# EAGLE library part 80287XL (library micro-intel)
MICROCOMPUTER/PERIPHERAL DEVICE

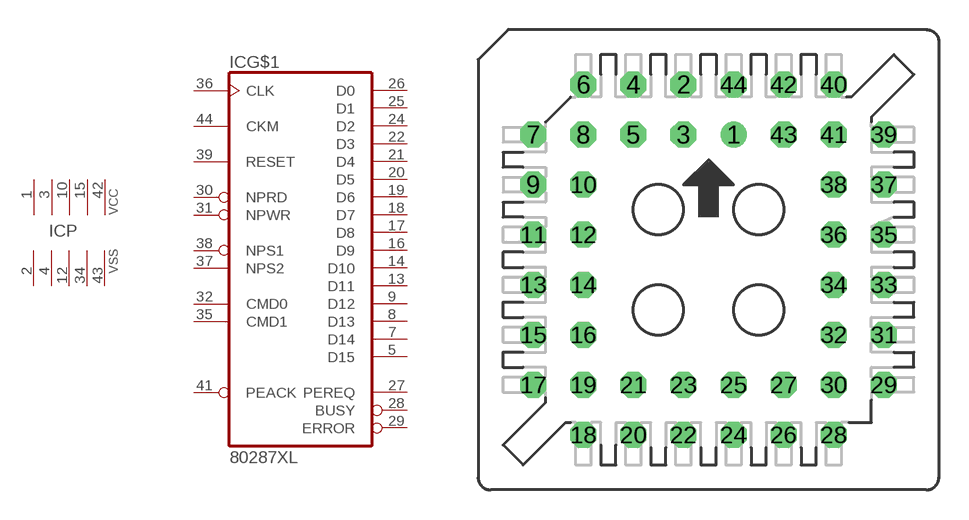
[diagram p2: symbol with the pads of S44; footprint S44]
Designator prefix IC; gates G$1=80287XL P=5VCC5VSS

## 80287XL (OC_FARNELL: unknown; OC_NEWARK: unknown)  [S44]
1  P:VCC  pwr
2  P:VSS  pwr
3  P:VCC  pwr
4  P:VSS  pwr
5  G$1:D15
7  G$1:D14
8  G$1:D13
9  G$1:D12
10  P:VCC  pwr
12  P:VSS  pwr
13  G$1:D11
14  G$1:D10
15  P:VCC  pwr
16  G$1:D9
17  G$1:D8
18  G$1:D7
19  G$1:D6
20  G$1:D5
21  G$1:D4
22  G$1:D3
24  G$1:D2
25  G$1:D1
26  G$1:D0
27  G$1:PEREQ  out
28  G$1:BUSY  out
29  G$1:ERROR  out
30  G$1:NPRD  in
31  G$1:NPWR  in
32  G$1:CMD0  in
34  P:VSS  pwr
35  G$1:CMD1  in
36  G$1:CLK  in
37  G$1:NPS2  in
38  G$1:NPS1  in
39  G$1:RESET  in
41  G$1:PEACK  in
42  P:VCC  pwr
43  P:VSS  pwr
44  G$1:CKM  in

## Footprint S44 (pad centres in mm)
PLCC SOCKET
drill 0.813 round: 1 1.27,6.35
drill 0.813 octagon: 2 -1.27,8.89; 3 -1.27,6.35; 4 -3.81,8.89; 5 -3.81,6.35; 6 -6.35,8.89; 7 -8.89,6.35; 8 -6.35,6.35; 9 -8.89,3.81; 10 -6.35,3.81; 11 -8.89,1.27; 12 -6.35,1.27; 13 -8.89,-1.27; 14 -6.35,-1.27; 15 -8.89,-3.81; 16 -6.35,-3.81; 17 -8.89,-6.35; 18 -6.35,-8.89; 19 -6.35,-6.35; 20 -3.81,-8.89; 21 -3.81,-6.35; 22 -1.27,-8.89; 23 -1.27,-6.35; 24 1.27,-8.89; 25 1.27,-6.35; 26 3.81,-8.89; 27 3.81,-6.35; 28 6.35,-8.89; 29 8.89,-6.35; 30 6.35,-6.35; 31 8.89,-3.81; 32 6.35,-3.81; 33 8.89,-1.27; 34 6.35,-1.27; 35 8.89,1.27; 36 6.35,1.27; 37 8.89,3.81; 38 6.35,3.81; 39 8.89,6.35; 40 6.35,8.89; 41 6.35,6.35; 42 3.81,8.89; 43 3.81,6.35; 44 1.27,8.89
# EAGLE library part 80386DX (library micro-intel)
MICROCOMPUTER/PERIPHERAL DEVICE

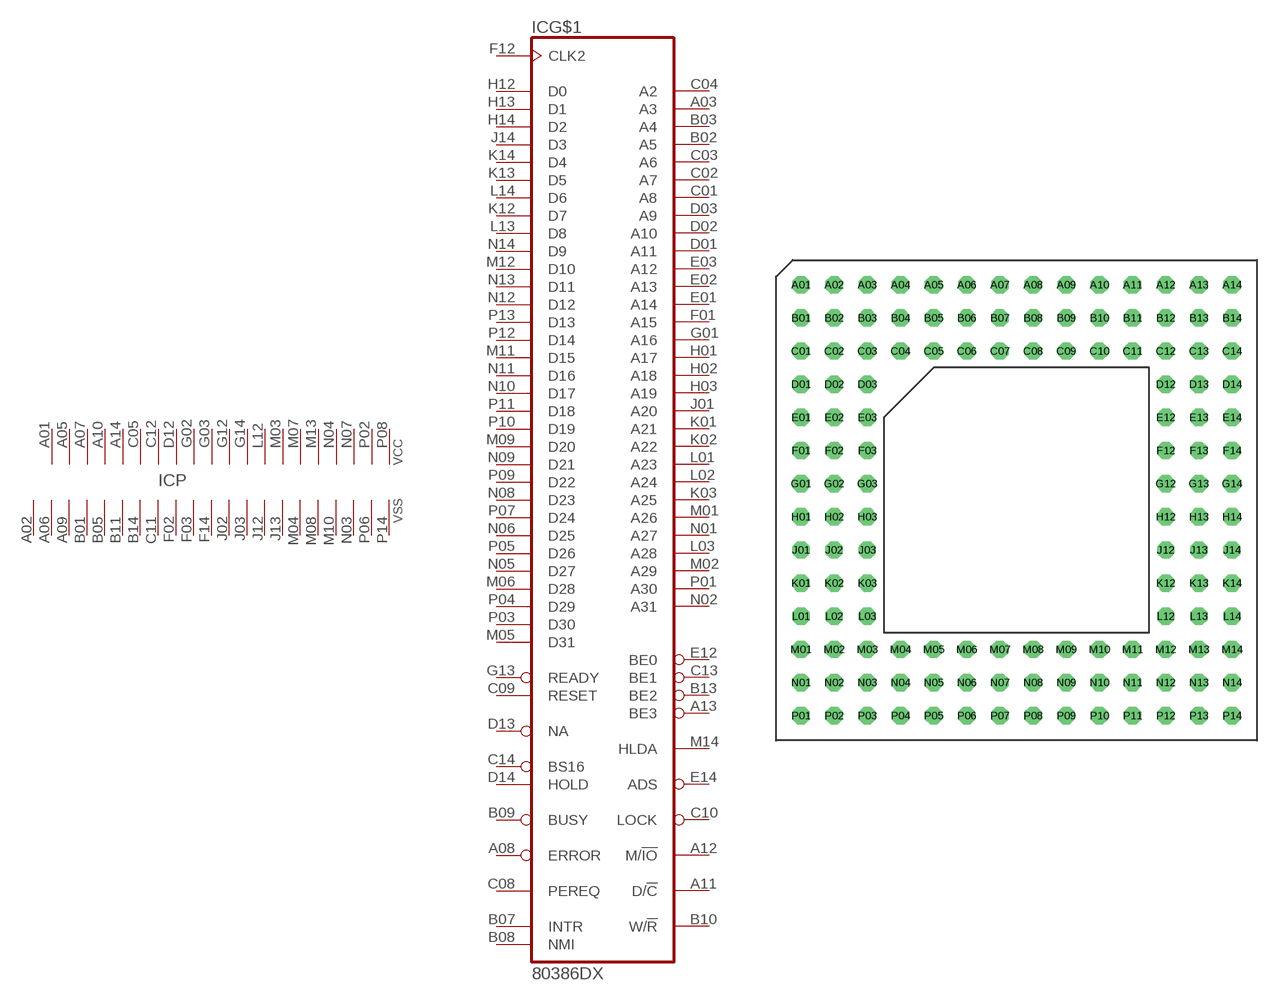
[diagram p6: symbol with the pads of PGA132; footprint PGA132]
Designator prefix IC; gates G$1=80386DX P=20VC21VS

## 80386DX (OC_FARNELL: unknown; OC_NEWARK: unknown)  [PGA132]
A01  P:VCC  pwr
A02  P:VSS  pwr
A03  G$1:A3  out
A05  P:VCC  pwr
A06  P:VSS  pwr
A07  P:VCC  pwr
A08  G$1:ERROR  in
A09  P:VSS  pwr
A10  P:VCC  pwr
A11  G$1:D/!C  out
A12  G$1:M/!IO  out
A13  G$1:BE3  out
A14  P:VCC  pwr
B01  P:VSS  pwr
B02  G$1:A5  out
B03  G$1:A4  out
B05  P:VSS  pwr
B07  G$1:INTR  in
B08  G$1:NMI  in
B09  G$1:BUSY  in
B10  G$1:W/!R  out
B11  P:VSS  pwr
B13  G$1:BE2  out
B14  P:VSS  pwr
C01  G$1:A8  out
C02  G$1:A7  out
C03  G$1:A6  out
C04  G$1:A2  out
C05  P:VCC  pwr
C08  G$1:PEREQ  in
C09  G$1:RESET  in
C10  G$1:LOCK  out
C11  P:VSS  pwr
C12  P:VCC  pwr
C13  G$1:BE1  out
C14  G$1:BS16  in
D01  G$1:A11  out
D02  G$1:A10  out
D03  G$1:A9  out
D12  P:VCC  pwr
D13  G$1:NA  in
D14  G$1:HOLD  in
E01  G$1:A14  out
E02  G$1:A13  out
E03  G$1:A12  out
E12  G$1:BE0  out
E14  G$1:ADS  out
F01  G$1:A15  out
F02  P:VSS  pwr
F03  P:VSS  pwr
F12  G$1:CLK2  in
F14  P:VSS  pwr
G01  G$1:A16  out
G02  P:VCC  pwr
G03  P:VCC  pwr
G12  P:VCC  pwr
G13  G$1:READY  in
G14  P:VCC  pwr
H01  G$1:A17  out
H02  G$1:A18  out
H03  G$1:A19  out
H12  G$1:D0
H13  G$1:D1
H14  G$1:D2
J01  G$1:A20  out
J02  P:VSS  pwr
J03  P:VSS  pwr
J12  P:VSS  pwr
J13  P:VSS  pwr
J14  G$1:D3
K01  G$1:A21  out
K02  G$1:A22  out
K03  G$1:A25  out
K12  G$1:D7
K13  G$1:D5
K14  G$1:D4
L01  G$1:A23  out
L02  G$1:A24  out
L03  G$1:A28  out
L12  P:VCC  pwr
L13  G$1:D8
L14  G$1:D6
M01  G$1:A26  out
M02  G$1:A29  out
M03  P:VCC  pwr
M04  P:VSS  pwr
M05  G$1:D31
M06  G$1:D28
M07  P:VCC  pwr
M08  P:VSS  pwr
M09  G$1:D20
M10  P:VSS  pwr
M11  G$1:D15
M12  G$1:D10
M13  P:VCC  pwr
M14  G$1:HLDA  out
N01  G$1:A27  out
N02  G$1:A31  out
N03  P:VSS  pwr
N04  P:VCC  pwr
N05  G$1:D27
N06  G$1:D25
N07  P:VCC  pwr
N08  G$1:D23
N09  G$1:D21
N10  G$1:D17
N11  G$1:D16
N12  G$1:D12
N13  G$1:D11
N14  G$1:D9
P01  G$1:A30  out
P02  P:VCC  pwr
P03  G$1:D30
P04  G$1:D29
P05  G$1:D26
P06  P:VSS  pwr
P07  G$1:D24
P08  P:VCC  pwr
P09  G$1:D22
P10  G$1:D19
P11  G$1:D18
P12  G$1:D14
P13  G$1:D13
P14  P:VSS  pwr

## Footprint PGA132 (pad centres in mm)
Pin Grid Array
drill 0.813 octagon: A01 -16.51,16.51; A02 -13.97,16.51; A03 -11.43,16.51; A04 -8.89,16.51; A05 -6.35,16.51; A06 -3.81,16.51; A07 -1.27,16.51; A08 1.27,16.51; A09 3.81,16.51; A10 6.35,16.51; A11 8.89,16.51; A12 11.43,16.51; A13 13.97,16.51; A14 16.51,16.51; B01 -16.51,13.97; B02 -13.97,13.97; B03 -11.43,13.97; B04 -8.89,13.97; B05 -6.35,13.97; B06 -3.81,13.97; B07 -1.27,13.97; B08 1.27,13.97; B09 3.81,13.97; B10 6.35,13.97; B11 8.89,13.97; B12 11.43,13.97; B13 13.97,13.97; B14 16.51,13.97; C01 -16.51,11.43; C02 -13.97,11.43; C03 -11.43,11.43; C04 -8.89,11.43; C05 -6.35,11.43; C06 -3.81,11.43; C07 -1.27,11.43; C08 1.27,11.43; C09 3.81,11.43; C10 6.35,11.43; C11 8.89,11.43; C12 11.43,11.43; C13 13.97,11.43; C14 16.51,11.43; D01 -16.51,8.89; D02 -13.97,8.89; D03 -11.43,8.89; D12 11.43,8.89; D13 13.97,8.89; D14 16.51,8.89; E01 -16.51,6.35; E02 -13.97,6.35; E03 -11.43,6.35; E12 11.43,6.35; E13 13.97,6.35; E14 16.51,6.35; F01 -16.51,3.81; F02 -13.97,3.81; F03 -11.43,3.81; F12 11.43,3.81; F13 13.97,3.81; F14 16.51,3.81; G01 -16.51,1.27; G02 -13.97,1.27; G03 -11.43,1.27; G12 11.43,1.27; G13 13.97,1.27; G14 16.51,1.27; H01 -16.51,-1.27; H02 -13.97,-1.27; H03 -11.43,-1.27; H12 11.43,-1.27; H13 13.97,-1.27; H14 16.51,-1.27; J01 -16.51,-3.81; J02 -13.97,-3.81; J03 -11.43,-3.81; J12 11.43,-3.81; J13 13.97,-3.81; J14 16.51,-3.81; K01 -16.51,-6.35; K02 -13.97,-6.35; K03 -11.43,-6.35; K12 11.43,-6.35; K13 13.97,-6.35; K14 16.51,-6.35; L01 -16.51,-8.89; L02 -13.97,-8.89; L03 -11.43,-8.89; L12 11.43,-8.89; L13 13.97,-8.89; L14 16.51,-8.89; M01 -16.51,-11.43; M02 -13.97,-11.43; M03 -11.43,-11.43; M04 -8.89,-11.43; M05 -6.35,-11.43; M06 -3.81,-11.43; M07 -1.27,-11.43; M08 1.27,-11.43; M09 3.81,-11.43; M10 6.35,-11.43; M11 8.89,-11.43; M12 11.43,-11.43; M13 13.97,-11.43; M14 16.51,-11.43; N01 -16.51,-13.97; N02 -13.97,-13.97; N03 -11.43,-13.97; N04 -8.89,-13.97; N05 -6.35,-13.97; N06 -3.81,-13.97; N07 -1.27,-13.97; N08 1.27,-13.97; N09 3.81,-13.97; N10 6.35,-13.97; N11 8.89,-13.97; N12 11.43,-13.97; N13 13.97,-13.97; N14 16.51,-13.97; P01 -16.51,-16.51; P02 -13.97,-16.51; P03 -11.43,-16.51; P04 -8.89,-16.51; P05 -6.35,-16.51; P06 -3.81,-16.51; P07 -1.27,-16.51; P08 1.27,-16.51; P09 3.81,-16.51; P10 6.35,-16.51; P11 8.89,-16.51; P12 11.43,-16.51; P13 13.97,-16.51; P14 16.51,-16.51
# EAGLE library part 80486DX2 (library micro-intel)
MICROCOMPUTER/PERIPHERAL DEVICE

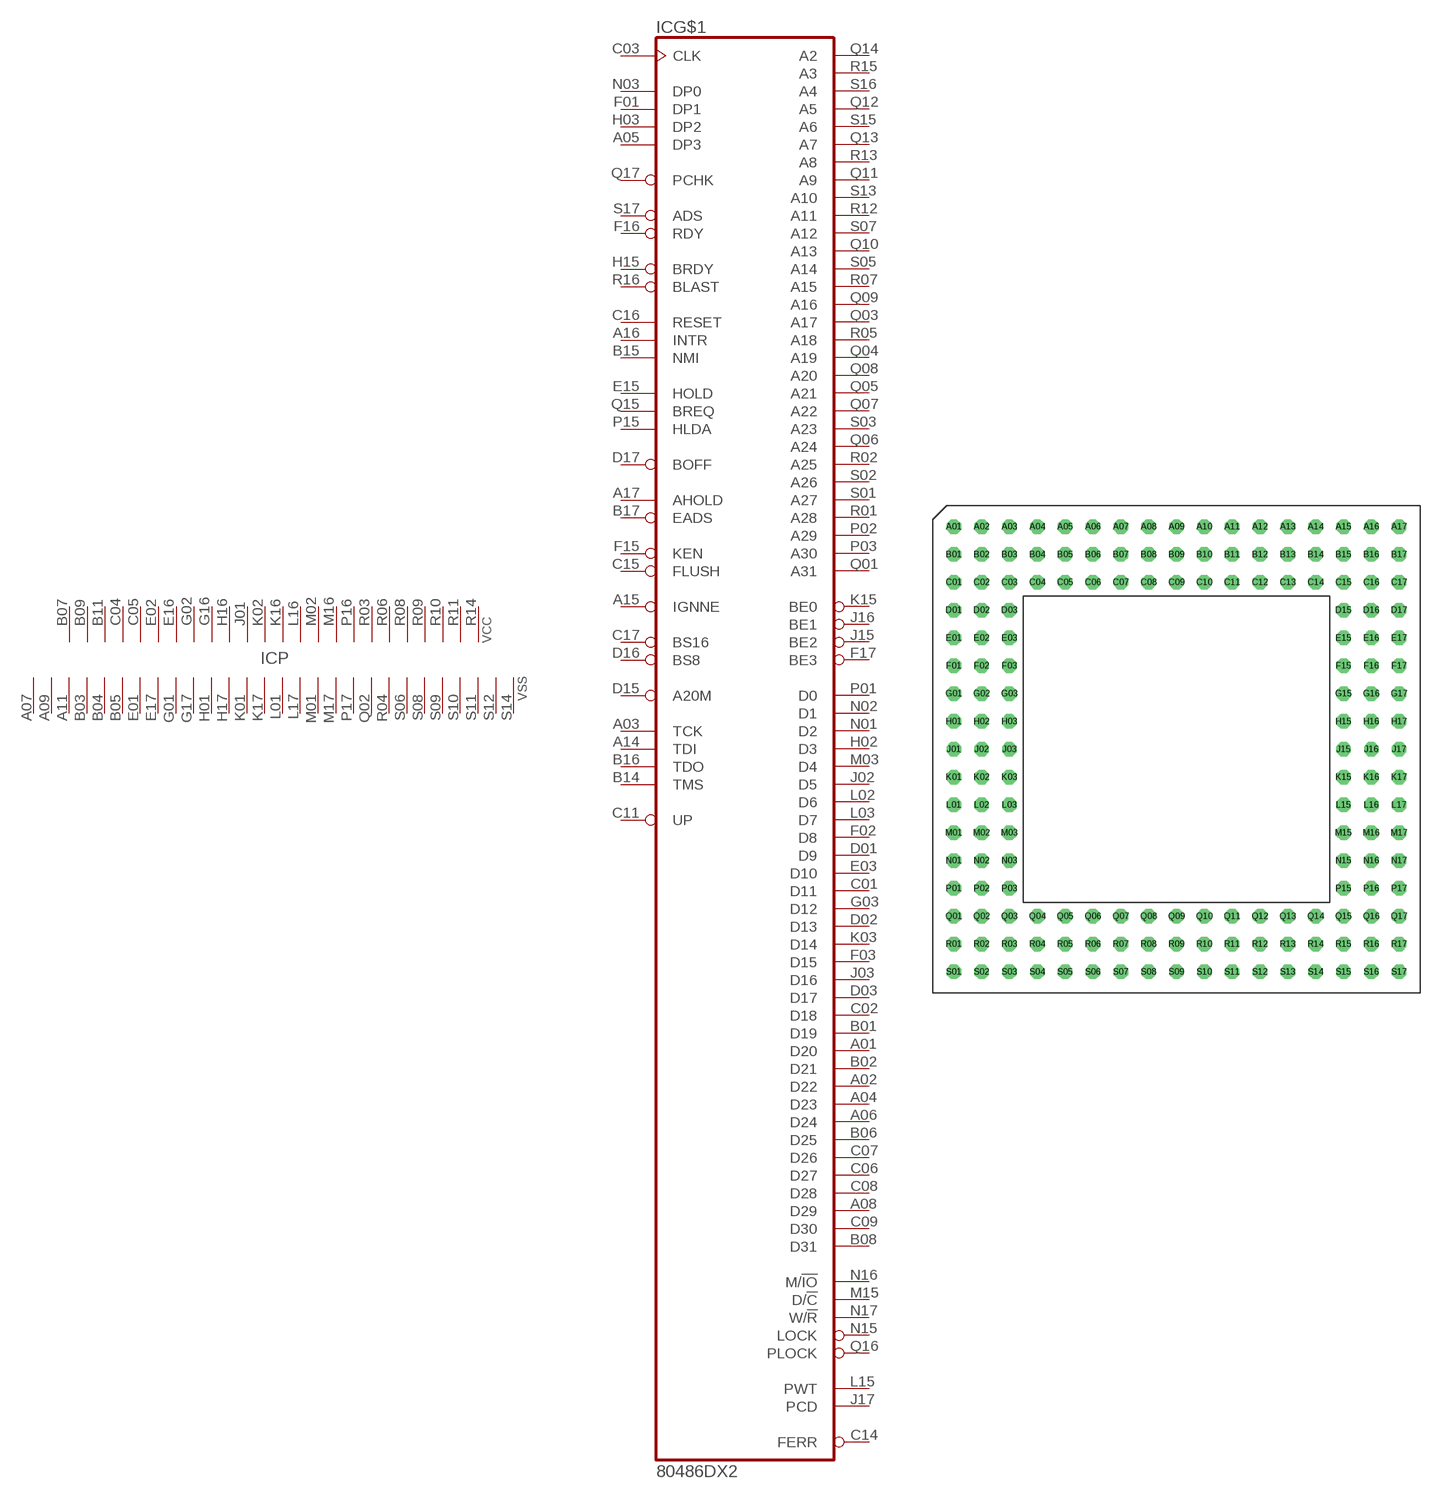
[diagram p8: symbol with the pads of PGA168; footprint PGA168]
Designator prefix IC; gates G$1=80486DX2 P=24VC28VS

## 80486DX2 (OC_FARNELL: unknown; OC_NEWARK: unknown)  [PGA168]
A01  G$1:D20
A02  G$1:D22
A03  G$1:TCK  in
A04  G$1:D23
A05  G$1:DP3
A06  G$1:D24
A07  P:VSS  pwr
A08  G$1:D29
A09  P:VSS  pwr
A11  P:VSS  pwr
A14  G$1:TDI  in
A15  G$1:IGNNE  in
A16  G$1:INTR  in
A17  G$1:AHOLD  in
B01  G$1:D19
B02  G$1:D21
B03  P:VSS  pwr
B04  P:VSS  pwr
B05  P:VSS  pwr
B06  G$1:D25
B07  P:VCC  pwr
B08  G$1:D31
B09  P:VCC  pwr
B11  P:VCC  pwr
B14  G$1:TMS  in
B15  G$1:NMI  in
B16  G$1:TDO  in
B17  G$1:EADS  in
C01  G$1:D11
C02  G$1:D18
C03  G$1:CLK  in
C04  P:VCC  pwr
C05  P:VCC  pwr
C06  G$1:D27
C07  G$1:D26
C08  G$1:D28
C09  G$1:D30
C11  G$1:UP  in
C14  G$1:FERR  out
C15  G$1:FLUSH  in
C16  G$1:RESET  in
C17  G$1:BS16  in
D01  G$1:D9
D02  G$1:D13
D03  G$1:D17
D15  G$1:A20M  in
D16  G$1:BS8  in
D17  G$1:BOFF  in
E01  P:VSS  pwr
E02  P:VCC  pwr
E03  G$1:D10
E15  G$1:HOLD  in
E16  P:VCC  pwr
E17  P:VSS  pwr
F01  G$1:DP1
F02  G$1:D8
F03  G$1:D15
F15  G$1:KEN  in
F16  G$1:RDY  in
F17  G$1:BE3  out
G01  P:VSS  pwr
G02  P:VCC  pwr
G03  G$1:D12
G16  P:VCC  pwr
G17  P:VSS  pwr
H01  P:VSS  pwr
H02  G$1:D3
H03  G$1:DP2
H15  G$1:BRDY  in
H16  P:VCC  pwr
H17  P:VSS  pwr
J01  P:VCC  pwr
J02  G$1:D5
J03  G$1:D16
J15  G$1:BE2  out
J16  G$1:BE1  out
J17  G$1:PCD  out
K01  P:VSS  pwr
K02  P:VCC  pwr
K03  G$1:D14
K15  G$1:BE0  out
K16  P:VCC  pwr
K17  P:VSS  pwr
L01  P:VSS  pwr
L02  G$1:D6
L03  G$1:D7
L15  G$1:PWT  out
L16  P:VCC  pwr
L17  P:VSS  pwr
M01  P:VSS  pwr
M02  P:VCC  pwr
M03  G$1:D4
M15  G$1:D/!C  out
M16  P:VCC  pwr
M17  P:VSS  pwr
N01  G$1:D2
N02  G$1:D1
N03  G$1:DP0
N15  G$1:LOCK  out
N16  G$1:M/!IO  out
N17  G$1:W/!R  out
P01  G$1:D0
P02  G$1:A29
P03  G$1:A30
P15  G$1:HLDA  out
P16  P:VCC  pwr
P17  P:VSS  pwr
Q01  G$1:A31
Q02  P:VSS  pwr
Q03  G$1:A17
Q04  G$1:A19
Q05  G$1:A21
Q06  G$1:A24
Q07  G$1:A22
Q08  G$1:A20
Q09  G$1:A16
Q10  G$1:A13
Q11  G$1:A9
Q12  G$1:A5
Q13  G$1:A7
Q14  G$1:A2  out
Q15  G$1:BREQ  out
Q16  G$1:PLOCK  out
Q17  G$1:PCHK  out
R01  G$1:A28
R02  G$1:A25
R03  P:VCC  pwr
R04  P:VSS  pwr
R05  G$1:A18
R06  P:VCC  pwr
R07  G$1:A15
R08  P:VCC  pwr
R09  P:VCC  pwr
R10  P:VCC  pwr
R11  P:VCC  pwr
R12  G$1:A11
R13  G$1:A8
R14  P:VCC  pwr
R15  G$1:A3  out
R16  G$1:BLAST  out
S01  G$1:A27
S02  G$1:A26
S03  G$1:A23
S05  G$1:A14
S06  P:VSS  pwr
S07  G$1:A12
S08  P:VSS  pwr
S09  P:VSS  pwr
S10  P:VSS  pwr
S11  P:VSS  pwr
S12  P:VSS  pwr
S13  G$1:A10
S14  P:VSS  pwr
S15  G$1:A6
S16  G$1:A4
S17  G$1:ADS  out

## Footprint PGA168 (pad centres in mm)
Pin Grid Array
drill 0.813 octagon: A01 -20.32,20.32; A02 -17.78,20.32; A03 -15.24,20.32; A04 -12.7,20.32; A05 -10.16,20.32; A06 -7.62,20.32; A07 -5.08,20.32; A08 -2.54,20.32; A09 0,20.32; A10 2.54,20.32; A11 5.08,20.32; A12 7.62,20.32; A13 10.16,20.32; A14 12.7,20.32; A15 15.24,20.32; A16 17.78,20.32; A17 20.32,20.32; B01 -20.32,17.78; B02 -17.78,17.78; B03 -15.24,17.78; B04 -12.7,17.78; B05 -10.16,17.78; B06 -7.62,17.78; B07 -5.08,17.78; B08 -2.54,17.78; B09 0,17.78; B10 2.54,17.78; B11 5.08,17.78; B12 7.62,17.78; B13 10.16,17.78; B14 12.7,17.78; B15 15.24,17.78; B16 17.78,17.78; B17 20.32,17.78; C01 -20.32,15.24; C02 -17.78,15.24; C03 -15.24,15.24; C04 -12.7,15.24; C05 -10.16,15.24; C06 -7.62,15.24; C07 -5.08,15.24; C08 -2.54,15.24; C09 0,15.24; C10 2.54,15.24; C11 5.08,15.24; C12 7.62,15.24; C13 10.16,15.24; C14 12.7,15.24; C15 15.24,15.24; C16 17.78,15.24; C17 20.32,15.24; D01 -20.32,12.7; D02 -17.78,12.7; D03 -15.24,12.7; D15 15.24,12.7; D16 17.78,12.7; D17 20.32,12.7; E01 -20.32,10.16; E02 -17.78,10.16; E03 -15.24,10.16; E15 15.24,10.16; E16 17.78,10.16; E17 20.32,10.16; F01 -20.32,7.62; F02 -17.78,7.62; F03 -15.24,7.62; F15 15.24,7.62; F16 17.78,7.62; F17 20.32,7.62; G01 -20.32,5.08; G02 -17.78,5.08; G03 -15.24,5.08; G15 15.24,5.08; G16 17.78,5.08; G17 20.32,5.08; H01 -20.32,2.54; H02 -17.78,2.54; H03 -15.24,2.54; H15 15.24,2.54; H16 17.78,2.54; H17 20.32,2.54; J01 -20.32,0; J02 -17.78,0; J03 -15.24,0; J15 15.24,0; J16 17.78,0; J17 20.32,0; K01 -20.32,-2.54; K02 -17.78,-2.54; K03 -15.24,-2.54; K15 15.24,-2.54; K16 17.78,-2.54; K17 20.32,-2.54; L01 -20.32,-5.08; L02 -17.78,-5.08; L03 -15.24,-5.08; L15 15.24,-5.08; L16 17.78,-5.08; L17 20.32,-5.08; M01 -20.32,-7.62; M02 -17.78,-7.62; M03 -15.24,-7.62; M15 15.24,-7.62; M16 17.78,-7.62; M17 20.32,-7.62; N01 -20.32,-10.16; N02 -17.78,-10.16; N03 -15.24,-10.16; N15 15.24,-10.16; N16 17.78,-10.16; N17 20.32,-10.16; P01 -20.32,-12.7; P02 -17.78,-12.7; P03 -15.24,-12.7; P15 15.24,-12.7; P16 17.78,-12.7; P17 20.32,-12.7; Q01 -20.32,-15.24; Q02 -17.78,-15.24; Q03 -15.24,-15.24; Q04 -12.7,-15.24; Q05 -10.16,-15.24; Q06 -7.62,-15.24; Q07 -5.08,-15.24; Q08 -2.54,-15.24; Q09 0,-15.24; Q10 2.54,-15.24; Q11 5.08,-15.24; Q12 7.62,-15.24; Q13 10.16,-15.24; Q14 12.7,-15.24; Q15 15.24,-15.24; Q16 17.78,-15.24; Q17 20.32,-15.24; R01 -20.32,-17.78; R02 -17.78,-17.78; R03 -15.24,-17.78; R04 -12.7,-17.78; R05 -10.16,-17.78; R06 -7.62,-17.78; R07 -5.08,-17.78; R08 -2.54,-17.78; R09 0,-17.78; R10 2.54,-17.78; R11 5.08,-17.78; R12 7.62,-17.78; R13 10.16,-17.78; R14 12.7,-17.78; R15 15.24,-17.78; R16 17.78,-17.78; R17 20.32,-17.78; S01 -20.32,-20.32; S02 -17.78,-20.32; S03 -15.24,-20.32; S04 -12.7,-20.32; S05 -10.16,-20.32; S06 -7.62,-20.32; S07 -5.08,-20.32; S08 -2.54,-20.32; S09 0,-20.32; S10 2.54,-20.32; S11 5.08,-20.32; S12 7.62,-20.32; S13 10.16,-20.32; S14 12.7,-20.32; S15 15.24,-20.32; S16 17.78,-20.32; S17 20.32,-20.32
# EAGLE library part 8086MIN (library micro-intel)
MICROCOMPUTER/PERIPHERAL DEVICE

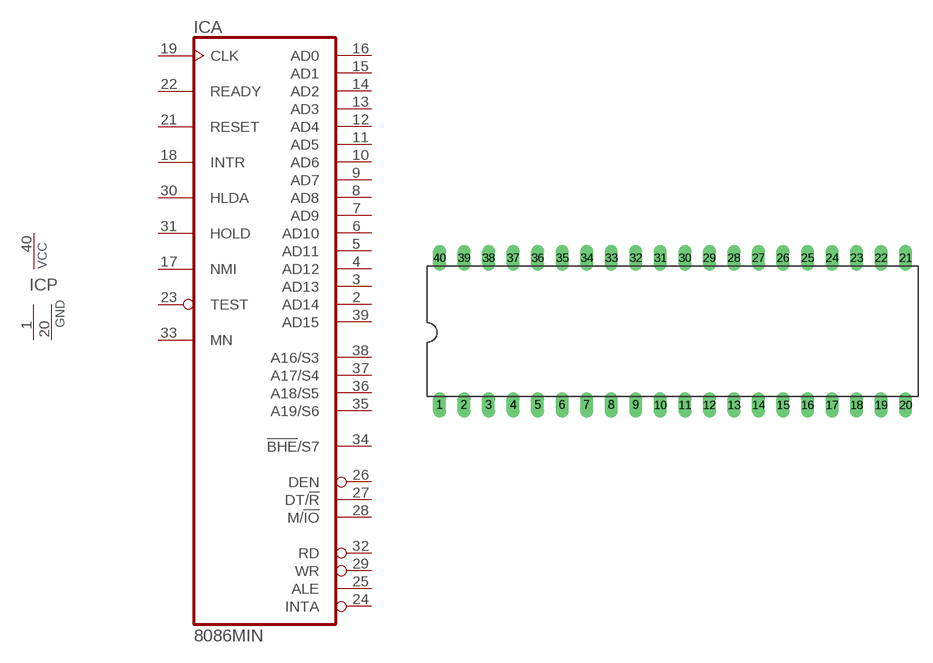
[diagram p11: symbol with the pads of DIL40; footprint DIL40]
Designator prefix IC; gates A=8086MIN P=PWR2GND

## 8086MIN (OC_FARNELL: unknown; OC_NEWARK: unknown)  [DIL40]
1  P:GND  pwr
2  A:AD14
3  A:AD13
4  A:AD12
5  A:AD11
6  A:AD10
7  A:AD9
8  A:AD8
9  A:AD7
10  A:AD6
11  A:AD5
12  A:AD4
13  A:AD3
14  A:AD2
15  A:AD1
16  A:AD0
17  A:NMI  in
18  A:INTR  in
19  A:CLK  in
20  P:GND  pwr
21  A:RESET  in
22  A:READY  in
23  A:TEST  in
24  A:INTA  out
25  A:ALE  out
26  A:DEN  out
27  A:DT/!R  out
28  A:M/!IO  out
29  A:WR  out
30  A:HLDA  out
31  A:HOLD  in
32  A:RD  out
33  A:MN  in
34  A:!BHE!/S7  out
35  A:A19/S6  out
36  A:A18/S5  out
37  A:A17/S4  out
38  A:A16/S3  out
39  A:AD15
40  P:VCC  pwr

## Footprint DIL40 (pad centres in mm)
Dual In Line Package
drill 0.813 long: 1 -24.13,-7.62; 2 -21.59,-7.62; 3 -19.05,-7.62; 4 -16.51,-7.62; 5 -13.97,-7.62; 6 -11.43,-7.62; 7 -8.89,-7.62; 8 -6.35,-7.62; 9 -3.81,-7.62; 10 -1.27,-7.62; 11 1.27,-7.62; 12 3.81,-7.62; 13 6.35,-7.62; 14 8.89,-7.62; 15 11.43,-7.62; 16 13.97,-7.62; 17 16.51,-7.62; 18 19.05,-7.62; 19 21.59,-7.62; 20 24.13,-7.62; 21 24.13,7.62; 22 21.59,7.62; 23 19.05,7.62; 24 16.51,7.62; 25 13.97,7.62; 26 11.43,7.62; 27 8.89,7.62; 28 6.35,7.62; 29 3.81,7.62; 30 1.27,7.62; 31 -1.27,7.62; 32 -3.81,7.62; 33 -6.35,7.62; 34 -8.89,7.62; 35 -11.43,7.62; 36 -13.97,7.62; 37 -16.51,7.62; 38 -19.05,7.62; 39 -21.59,7.62; 40 -24.13,7.62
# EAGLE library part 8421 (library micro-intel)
MICROCOMPUTER/PERIPHERAL DEVICE

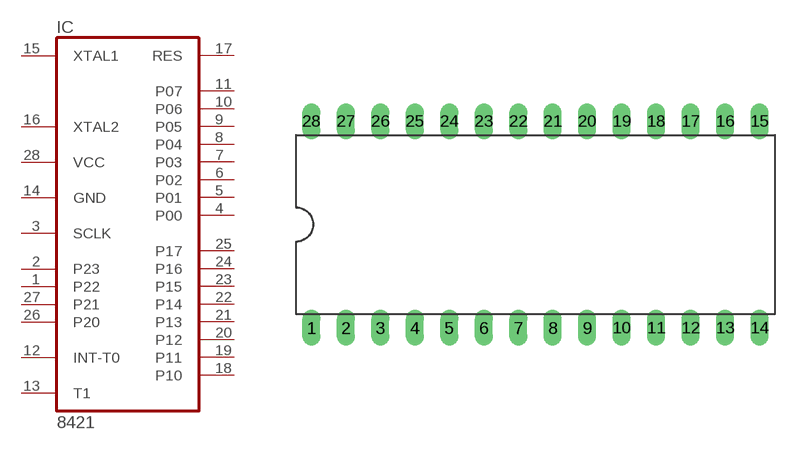
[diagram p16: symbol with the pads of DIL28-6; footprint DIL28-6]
Designator prefix IC

## 8421 (OC_FARNELL: unknown; OC_NEWARK: unknown)  [DIL28-6]
1  P22
2  P23
3  SCLK
4  P00
5  P01
6  P02
7  P03
8  P04
9  P05
10  P06
11  P07
12  INT-T0  in
13  T1  in
14  GND  pwr
15  XTAL1  in
16  XTAL2  in
17  RES
18  P10
19  P11
20  P12
21  P13
22  P14
23  P15
24  P16
25  P17
26  P20
27  P21
28  VCC  pwr

## Footprint DIL28-6 (pad centres in mm)
Dual In Line Package 0.6 inch
drill 0.813 long: 1 -16.51,-7.62; 2 -13.97,-7.62; 3 -11.43,-7.62; 4 -8.89,-7.62; 5 -6.35,-7.62; 6 -3.81,-7.62; 7 -1.27,-7.62; 8 1.27,-7.62; 9 3.81,-7.62; 10 6.35,-7.62; 11 8.89,-7.62; 12 11.43,-7.62; 13 13.97,-7.62; 14 16.51,-7.62; 15 16.51,7.62; 16 13.97,7.62; 17 11.43,7.62; 18 8.89,7.62; 19 6.35,7.62; 20 3.81,7.62; 21 1.27,7.62; 22 -1.27,7.62; 23 -3.81,7.62; 24 -6.35,7.62; 25 -8.89,7.62; 26 -11.43,7.62; 27 -13.97,7.62; 28 -16.51,7.62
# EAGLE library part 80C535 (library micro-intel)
MICROCOMPUTER/PERIPHERAL DEVICE

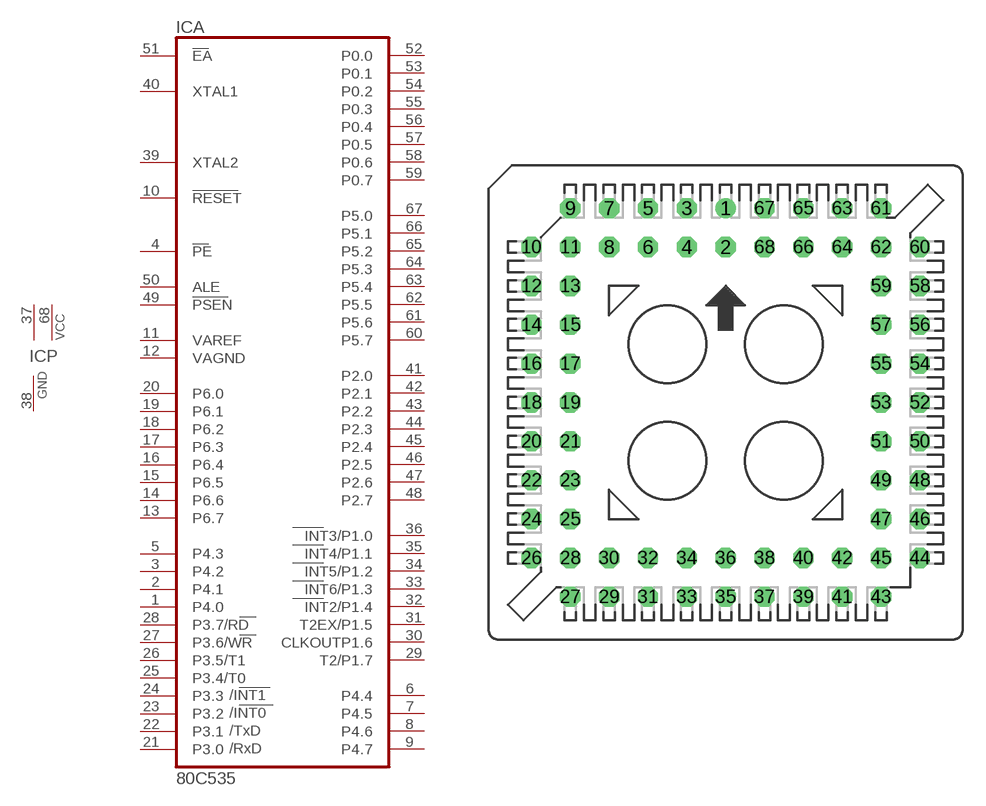
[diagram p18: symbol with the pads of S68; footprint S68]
Designator prefix IC; gates A=80C535 P=2VCC1GND

## 80C535 (OC_FARNELL: unknown; OC_NEWARK: unknown)  [S68]
1  A:P4.0
2  A:P4.1
3  A:P4.2
4  A:PE  in
5  A:P4.3
6  A:P4.4
7  A:P4.5
8  A:P4.6
9  A:P4.7
10  A:RESET  in
11  A:VAREF
12  A:VAGND
13  A:P6.7  in
14  A:P6.6  in
15  A:P6.5  in
16  A:P6.4  in
17  A:P6.3  in
18  A:P6.2  in
19  A:P6.1  in
20  A:P6.0  in
21  A:P3.0
22  A:P3.1
23  A:P3.2
24  A:P3.3
25  A:P3.4/T0
26  A:P3.5/T1
27  A:P3.6/WR
28  A:P3.7/RD
29  A:T2/P1.7
30  A:CLKOUTP1.6
31  A:T2EX/P1.5
32  A:INT2/P1.4
33  A:INT6/P1.3
34  A:INT5/P1.2
35  A:INT4/P1.1
36  A:INT3/P1.0
37  P:VCC  pwr
38  P:GND  pwr
39  A:XTAL2  in
40  A:XTAL1  in
41  A:P2.0
42  A:P2.1
43  A:P2.2
44  A:P2.3
45  A:P2.4
46  A:P2.5
47  A:P2.6
48  A:P2.7
49  A:PSEN  out
50  A:ALE  out
51  A:EA  in
52  A:P0.0
53  A:P0.1
54  A:P0.2
55  A:P0.3
56  A:P0.4
57  A:P0.5
58  A:P0.6
59  A:P0.7
60  A:P5.7
61  A:P5.6
62  A:P5.5
63  A:P5.4
64  A:P5.3
65  A:P5.2
66  A:P5.1
67  A:P5.0
68  P:VCC  pwr

## Footprint S68 (pad centres in mm)
PLCC SOCKET
drill 0.813 round: 1 0,12.7
drill 0.813 octagon: 2 0,10.16; 3 -2.54,12.7; 4 -2.54,10.16; 5 -5.08,12.7; 6 -5.08,10.16; 7 -7.62,12.7; 8 -7.62,10.16; 9 -10.16,12.7; 10 -12.7,10.16; 11 -10.16,10.16; 12 -12.7,7.62; 13 -10.16,7.62; 14 -12.7,5.08; 15 -10.16,5.08; 16 -12.7,2.54; 17 -10.16,2.54; 18 -12.7,0; 19 -10.16,0; 20 -12.7,-2.54; 21 -10.16,-2.54; 22 -12.7,-5.08; 23 -10.16,-5.08; 24 -12.7,-7.62; 25 -10.16,-7.62; 26 -12.7,-10.16; 27 -10.16,-12.7; 28 -10.16,-10.16; 29 -7.62,-12.7; 30 -7.62,-10.16; 31 -5.08,-12.7; 32 -5.08,-10.16; 33 -2.54,-12.7; 34 -2.54,-10.16; 35 0,-12.7; 36 0,-10.16; 37 2.54,-12.7; 38 2.54,-10.16; 39 5.08,-12.7; 40 5.08,-10.16; 41 7.62,-12.7; 42 7.62,-10.16; 43 10.16,-12.7; 44 12.7,-10.16; 45 10.16,-10.16; 46 12.7,-7.62; 47 10.16,-7.62; 48 12.7,-5.08; 49 10.16,-5.08; 50 12.7,-2.54; 51 10.16,-2.54; 52 12.7,0; 53 10.16,0; 54 12.7,2.54; 55 10.16,2.54; 56 12.7,5.08; 57 10.16,5.08; 58 12.7,7.62; 59 10.16,7.62; 60 12.7,10.16; 61 10.16,12.7; 62 10.16,10.16; 63 7.62,12.7; 64 7.62,10.16; 65 5.08,12.7; 66 5.08,10.16; 67 2.54,12.7; 68 2.54,10.16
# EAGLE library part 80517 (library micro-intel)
MICROCOMPUTER/PERIPHERAL DEVICE

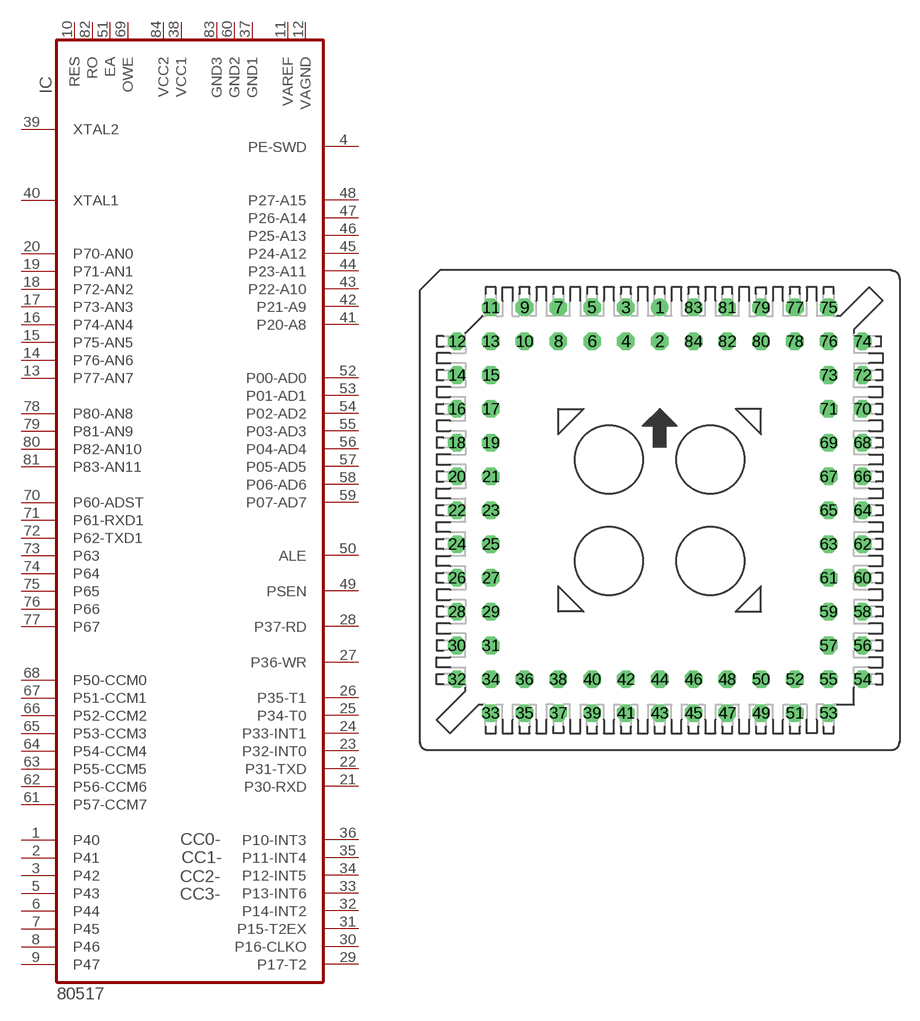
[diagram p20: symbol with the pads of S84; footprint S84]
Designator prefix IC

## 80517 (OC_FARNELL: unknown; OC_NEWARK: unknown)  [S84]
1  P40
2  P41
3  P42
4  PE-SWD  in
5  P43
6  P44
7  P45
8  P46
9  P47
10  RES  in
11  VAREF  pwr
12  VAGND  pwr
13  P77-AN7  in
14  P76-AN6  in
15  P75-AN5  in
16  P74-AN4  in
17  P73-AN3  in
18  P72-AN2  in
19  P71-AN1  in
20  P70-AN0  in
21  P30-RXD
22  P31-TXD
23  P32-INT0
24  P33-INT1
25  P34-T0
26  P35-T1
27  P36-WR
28  P37-RD
29  P17-T2
30  P16-CLKO
31  P15-T2EX
32  P14-INT2
33  P13-INT6
34  P12-INT5
35  P11-INT4
36  P10-INT3
37  GND1  pwr
38  VCC1  pwr
39  XTAL2  in
40  XTAL1  in
41  P20-A8
42  P21-A9
43  P22-A10
44  P23-A11
45  P24-A12
46  P25-A13
47  P26-A14
48  P27-A15
49  PSEN  out
50  ALE  out
51  EA  in
52  P00-AD0
53  P01-AD1
54  P02-AD2
55  P03-AD3
56  P04-AD4
57  P05-AD5
58  P06-AD6
59  P07-AD7
60  GND2  pwr
61  P57-CCM7
62  P56-CCM6
63  P55-CCM5
64  P54-CCM4
65  P53-CCM3
66  P52-CCM2
67  P51-CCM1
68  P50-CCM0
69  OWE  in
70  P60-ADST
71  P61-RXD1
72  P62-TXD1
73  P63
74  P64
75  P65
76  P66
77  P67
78  P80-AN8  in
79  P81-AN9  in
80  P82-AN10  in
81  P83-AN11  in
82  RO  out
83  GND3  pwr
84  VCC2  pwr

## Footprint S84 (pad centres in mm)
PLCC SOCKET
drill 0.813 round: 1 0,15.24
drill 0.813 octagon: 2 0,12.7; 3 -2.54,15.24; 4 -2.54,12.7; 5 -5.08,15.24; 6 -5.08,12.7; 7 -7.62,15.24; 8 -7.62,12.7; 9 -10.16,15.24; 10 -10.16,12.7; 11 -12.7,15.24; 12 -15.24,12.7; 13 -12.7,12.7; 14 -15.24,10.16; 15 -12.7,10.16; 16 -15.24,7.62; 17 -12.7,7.62; 18 -15.24,5.08; 19 -12.7,5.08; 20 -15.24,2.54; 21 -12.7,2.54; 22 -15.24,0; 23 -12.7,0; 24 -15.24,-2.54; 25 -12.7,-2.54; 26 -15.24,-5.08; 27 -12.7,-5.08; 28 -15.24,-7.62; 29 -12.7,-7.62; 30 -15.24,-10.16; 31 -12.7,-10.16; 32 -15.24,-12.7; 33 -12.7,-15.24; 34 -12.7,-12.7; 35 -10.16,-15.24; 36 -10.16,-12.7; 37 -7.62,-15.24; 38 -7.62,-12.7; 39 -5.08,-15.24; 40 -5.08,-12.7; 41 -2.54,-15.24; 42 -2.54,-12.7; 43 0,-15.24; 44 0,-12.7; 45 2.54,-15.24; 46 2.54,-12.7; 47 5.08,-15.24; 48 5.08,-12.7; 49 7.62,-15.24; 50 7.62,-12.7; 51 10.16,-15.24; 52 10.16,-12.7; 53 12.7,-15.24; 54 15.24,-12.7; 55 12.7,-12.7; 56 15.24,-10.16; 57 12.7,-10.16; 58 15.24,-7.62; 59 12.7,-7.62; 60 15.24,-5.08; 61 12.7,-5.08; 62 15.24,-2.54; 63 12.7,-2.54; 64 15.24,0; 65 12.7,0; 66 15.24,2.54; 67 12.7,2.54; 68 15.24,5.08; 69 12.7,5.08; 70 15.24,7.62; 71 12.7,7.62; 72 15.24,10.16; 73 12.7,10.16; 74 15.24,12.7; 75 12.7,15.24; 76 12.7,12.7; 77 10.16,15.24; 78 10.16,12.7; 79 7.62,15.24; 80 7.62,12.7; 81 5.08,15.24; 82 5.08,12.7; 83 2.54,15.24; 84 2.54,12.7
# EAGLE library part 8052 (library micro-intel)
MICROCOMPUTER/PERIPHERAL DEVICE 80C51/87C51/80C52/87C52 80C51 8-bit microcontroller family 4 K/8 K OTP/ROM low voltage (2.7 V-5.5 V), low power, high speed (33 MHz), 128/256 B RAM Source: www.semiconductors.philips.com .. 8XC51_8XC52_6.pdf

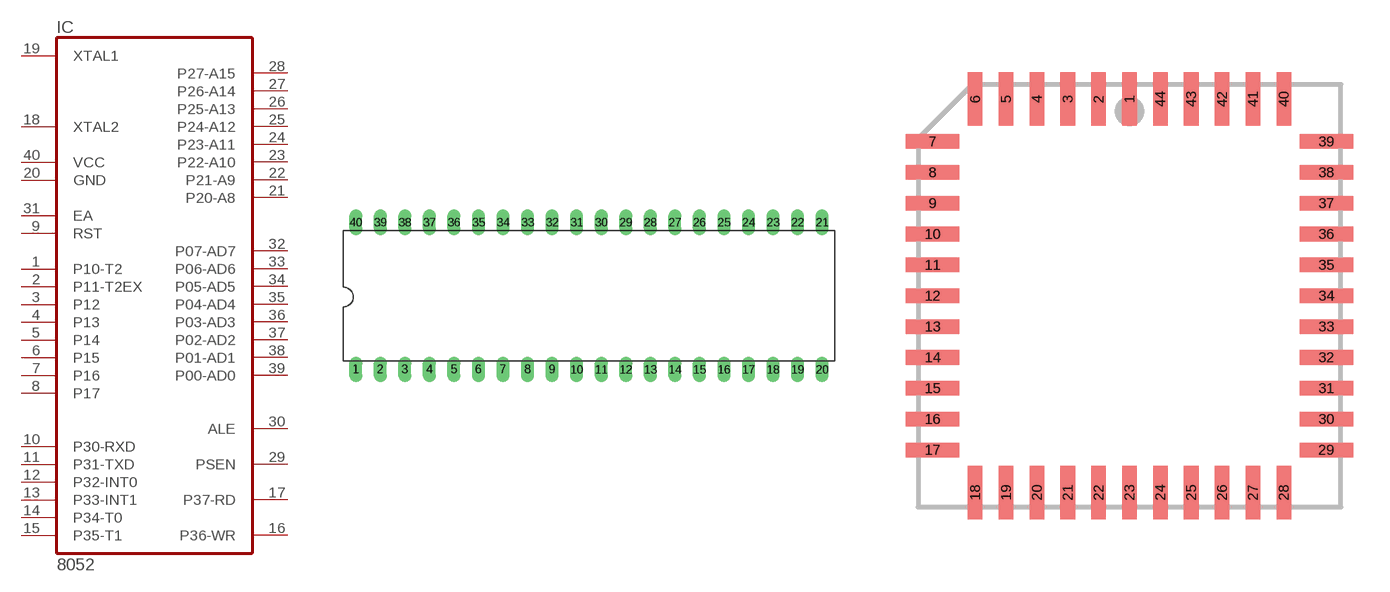
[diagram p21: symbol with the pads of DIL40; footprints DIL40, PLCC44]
Designator prefix IC

## 8052N (OC_FARNELL: unknown; OC_NEWARK: unknown)  [DIL40]
1  P10-T2
2  P11-T2EX
3  P12
4  P13
5  P14
6  P15
7  P16
8  P17
9  RST  in
10  P30-RXD
11  P31-TXD
12  P32-INT0
13  P33-INT1
14  P34-T0
15  P35-T1
16  P36-WR
17  P37-RD
18  XTAL2  in
19  XTAL1  in
20  GND  pwr
21  P20-A8
22  P21-A9
23  P22-A10
24  P23-A11
25  P24-A12
26  P25-A13
27  P26-A14
28  P27-A15
29  PSEN  out
30  ALE  out
31  EA  in
32  P07-AD7
33  P06-AD6
34  P05-AD5
35  P04-AD4
36  P03-AD3
37  P02-AD2
38  P01-AD1
39  P00-AD0
40  VCC  pwr

## 8052AA (OC_FARNELL: unknown; OC_NEWARK: unknown)  [PLCC44]
2  P10-T2
3  P11-T2EX
4  P12
5  P13
6  P14
7  P15
8  P16
9  P17
10  RST  in
11  P30-RXD
13  P31-TXD
14  P32-INT0
15  P33-INT1
16  P34-T0
17  P35-T1
18  P36-WR
19  P37-RD
20  XTAL2  in
21  XTAL1  in
22  GND  pwr
24  P20-A8
25  P21-A9
26  P22-A10
27  P23-A11
28  P24-A12
29  P25-A13
30  P26-A14
31  P27-A15
32  PSEN  out
33  ALE  out
35  EA  in
36  P07-AD7
37  P06-AD6
38  P05-AD5
39  P04-AD4
40  P03-AD3
41  P02-AD2
42  P01-AD1
43  P00-AD0
44  VCC  pwr

## 8052AA-SOCK (OC_FARNELL: unknown; OC_NEWARK: unknown)  [S44]
Pads as for PLCC44

## 8052BB (OC_FARNELL: unknown; OC_NEWARK: unknown)  [QFP44]
1  P15
2  P16
3  P17
4  RST  in
5  P30-RXD
7  P31-TXD
8  P32-INT0
9  P33-INT1
10  P34-T0
11  P35-T1
12  P36-WR
13  P37-RD
14  XTAL2  in
15  XTAL1  in
16  GND  pwr
18  P20-A8
19  P21-A9
20  P22-A10
21  P23-A11
22  P24-A12
23  P25-A13
24  P26-A14
25  P27-A15
26  PSEN  out
27  ALE  out
29  EA  in
30  P07-AD7
31  P06-AD6
32  P05-AD5
33  P04-AD4
34  P03-AD3
35  P02-AD2
36  P01-AD1
37  P00-AD0
38  VCC  pwr
40  P10-T2
41  P11-T2EX
42  P12
43  P13
44  P14

## Footprint DIL40 (pad centres in mm)
Dual In Line Package
drill 0.813 long: 1 -24.13,-7.62; 2 -21.59,-7.62; 3 -19.05,-7.62; 4 -16.51,-7.62; 5 -13.97,-7.62; 6 -11.43,-7.62; 7 -8.89,-7.62; 8 -6.35,-7.62; 9 -3.81,-7.62; 10 -1.27,-7.62; 11 1.27,-7.62; 12 3.81,-7.62; 13 6.35,-7.62; 14 8.89,-7.62; 15 11.43,-7.62; 16 13.97,-7.62; 17 16.51,-7.62; 18 19.05,-7.62; 19 21.59,-7.62; 20 24.13,-7.62; 21 24.13,7.62; 22 21.59,7.62; 23 19.05,7.62; 24 16.51,7.62; 25 13.97,7.62; 26 11.43,7.62; 27 8.89,7.62; 28 6.35,7.62; 29 3.81,7.62; 30 1.27,7.62; 31 -1.27,7.62; 32 -3.81,7.62; 33 -6.35,7.62; 34 -8.89,7.62; 35 -11.43,7.62; 36 -13.97,7.62; 37 -16.51,7.62; 38 -19.05,7.62; 39 -21.59,7.62; 40 -24.13,7.62

## Footprint PLCC44 (pad centres in mm)
PLASTIC LEADED CHIP CARRIER square
smd 0.6 x 2.2: 1 0,8.1; 2 -1.27,8.1; 3 -2.54,8.1; 4 -3.81,8.1; 5 -5.08,8.1; 6 -6.35,8.1; 18 -6.35,-8.1; 19 -5.08,-8.1; 20 -3.81,-8.1; 21 -2.54,-8.1; 22 -1.27,-8.1; 23 0,-8.1; 24 1.27,-8.1; 25 2.54,-8.1; 26 3.81,-8.1; 27 5.08,-8.1; 28 6.35,-8.1; 40 6.35,8.1; 41 5.08,8.1; 42 3.81,8.1; 43 2.54,8.1; 44 1.27,8.1
smd 2.2 x 0.6: 7 -8.1,6.35; 8 -8.1,5.08; 9 -8.1,3.81; 10 -8.1,2.54; 11 -8.1,1.27; 12 -8.1,0; 13 -8.1,-1.27; 14 -8.1,-2.54; 15 -8.1,-3.81; 16 -8.1,-5.08; 17 -8.1,-6.35; 29 8.1,-6.35; 30 8.1,-5.08; 31 8.1,-3.81; 32 8.1,-2.54; 33 8.1,-1.27; 34 8.1,0; 35 8.1,1.27; 36 8.1,2.54; 37 8.1,3.81; 38 8.1,5.08; 39 8.1,6.35

## Footprint S44 (pad centres in mm)
PLCC SOCKET
drill 0.813 round: 1 1.27,6.35
drill 0.813 octagon: 2 -1.27,8.89; 3 -1.27,6.35; 4 -3.81,8.89; 5 -3.81,6.35; 6 -6.35,8.89; 7 -8.89,6.35; 8 -6.35,6.35; 9 -8.89,3.81; 10 -6.35,3.81; 11 -8.89,1.27; 12 -6.35,1.27; 13 -8.89,-1.27; 14 -6.35,-1.27; 15 -8.89,-3.81; 16 -6.35,-3.81; 17 -8.89,-6.35; 18 -6.35,-8.89; 19 -6.35,-6.35; 20 -3.81,-8.89; 21 -3.81,-6.35; 22 -1.27,-8.89; 23 -1.27,-6.35; 24 1.27,-8.89; 25 1.27,-6.35; 26 3.81,-8.89; 27 3.81,-6.35; 28 6.35,-8.89; 29 8.89,-6.35; 30 6.35,-6.35; 31 8.89,-3.81; 32 6.35,-3.81; 33 8.89,-1.27; 34 6.35,-1.27; 35 8.89,1.27; 36 6.35,1.27; 37 8.89,3.81; 38 6.35,3.81; 39 8.89,6.35; 40 6.35,8.89; 41 6.35,6.35; 42 3.81,8.89; 43 3.81,6.35; 44 1.27,8.89

## Footprint QFP44 (pad centres in mm)
Plastic Quad Flat Package 44 leads lead length 1.3 mm; body 10 x 10 x 1.75 mm SOT307-2 Source: www.semiconductors.philips.com .. 8XC51_8XC52_6.pdf
smd 2.2 x 0.35: 1 -6.1,4; 2 -6.1,3.2; 3 -6.1,2.4; 4 -6.1,1.6; 5 -6.1,0.8; 6 -6.1,0; 7 -6.1,-0.8; 8 -6.1,-1.6; 9 -6.1,-2.4; 10 -6.1,-3.2; 11 -6.1,-4; 23 6.1,-4; 24 6.1,-3.2; 25 6.1,-2.4; 26 6.1,-1.6; 27 6.1,-0.8; 28 6.1,0; 29 6.1,0.8; 30 6.1,1.6; 31 6.1,2.4; 32 6.1,3.2; 33 6.1,4
smd 0.35 x 2.2: 12 -4,-6.1; 13 -3.2,-6.1; 14 -2.4,-6.1; 15 -1.6,-6.1; 16 -0.8,-6.1; 17 0,-6.1; 18 0.8,-6.1; 19 1.6,-6.1; 20 2.4,-6.1; 21 3.2,-6.1; 22 4,-6.1; 34 4,6.1; 35 3.2,6.1; 36 2.4,6.1; 37 1.6,6.1; 38 0.8,6.1; 39 0,6.1; 40 -0.8,6.1; 41 -1.6,6.1; 42 -2.4,6.1; 43 -3.2,6.1; 44 -4,6.1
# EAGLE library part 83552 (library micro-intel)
MICROCOMPUTER/PERIPHERAL DEVICE

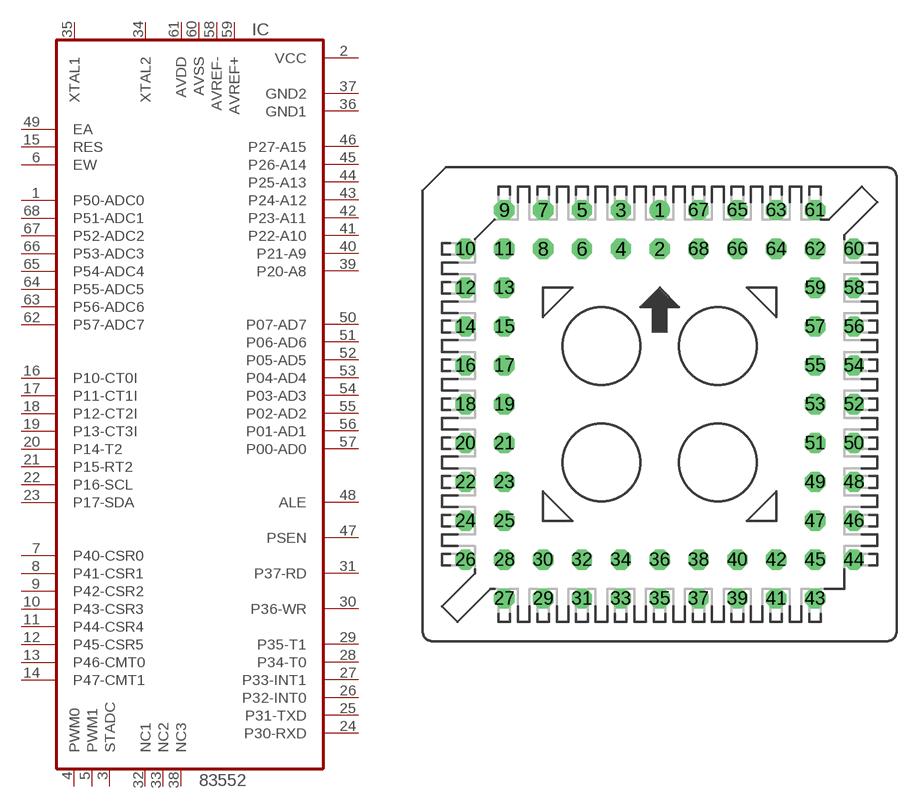
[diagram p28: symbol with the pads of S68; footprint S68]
Designator prefix IC

## 83552 (OC_FARNELL: unknown; OC_NEWARK: unknown)  [S68]
1  P50-ADC0  in
2  VCC  pwr
3  STADC  in
4  PWM0  out
5  PWM1  out
6  EW  in
7  P40-CSR0
8  P41-CSR1
9  P42-CSR2
10  P43-CSR3
11  P44-CSR4
12  P45-CSR5
13  P46-CMT0
14  P47-CMT1
15  RES
16  P10-CT0I
17  P11-CT1I
18  P12-CT2I
19  P13-CT3I
20  P14-T2
21  P15-RT2
22  P16-SCL
23  P17-SDA
24  P30-RXD
25  P31-TXD
26  P32-INT0
27  P33-INT1
28  P34-T0
29  P35-T1
30  P36-WR
31  P37-RD
32  NC1  nc
33  NC2  nc
34  XTAL2  in
35  XTAL1  in
36  GND1  pwr
37  GND2  pwr
38  NC3  nc
39  P20-A8
40  P21-A9
41  P22-A10
42  P23-A11
43  P24-A12
44  P25-A13
45  P26-A14
46  P27-A15
47  PSEN  out
48  ALE  out
49  EA  in
50  P07-AD7
51  P06-AD6
52  P05-AD5
53  P04-AD4
54  P03-AD3
55  P02-AD2
56  P01-AD1
57  P00-AD0
58  AVREF-  pwr
59  AVREF+  pwr
60  AVSS  pwr
61  AVDD  pwr
62  P57-ADC7  in
63  P56-ADC6  in
64  P55-ADC5  in
65  P54-ADC4  in
66  P53-ADC3  in
67  P52-ADC2  in
68  P51-ADC1  in

## Footprint S68 (pad centres in mm)
PLCC SOCKET
drill 0.813 round: 1 0,12.7
drill 0.813 octagon: 2 0,10.16; 3 -2.54,12.7; 4 -2.54,10.16; 5 -5.08,12.7; 6 -5.08,10.16; 7 -7.62,12.7; 8 -7.62,10.16; 9 -10.16,12.7; 10 -12.7,10.16; 11 -10.16,10.16; 12 -12.7,7.62; 13 -10.16,7.62; 14 -12.7,5.08; 15 -10.16,5.08; 16 -12.7,2.54; 17 -10.16,2.54; 18 -12.7,0; 19 -10.16,0; 20 -12.7,-2.54; 21 -10.16,-2.54; 22 -12.7,-5.08; 23 -10.16,-5.08; 24 -12.7,-7.62; 25 -10.16,-7.62; 26 -12.7,-10.16; 27 -10.16,-12.7; 28 -10.16,-10.16; 29 -7.62,-12.7; 30 -7.62,-10.16; 31 -5.08,-12.7; 32 -5.08,-10.16; 33 -2.54,-12.7; 34 -2.54,-10.16; 35 0,-12.7; 36 0,-10.16; 37 2.54,-12.7; 38 2.54,-10.16; 39 5.08,-12.7; 40 5.08,-10.16; 41 7.62,-12.7; 42 7.62,-10.16; 43 10.16,-12.7; 44 12.7,-10.16; 45 10.16,-10.16; 46 12.7,-7.62; 47 10.16,-7.62; 48 12.7,-5.08; 49 10.16,-5.08; 50 12.7,-2.54; 51 10.16,-2.54; 52 12.7,0; 53 10.16,0; 54 12.7,2.54; 55 10.16,2.54; 56 12.7,5.08; 57 10.16,5.08; 58 12.7,7.62; 59 10.16,7.62; 60 12.7,10.16; 61 10.16,12.7; 62 10.16,10.16; 63 7.62,12.7; 64 7.62,10.16; 65 5.08,12.7; 66 5.08,10.16; 67 2.54,12.7; 68 2.54,10.16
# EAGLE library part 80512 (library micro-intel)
MICROCOMPUTER/PERIPHERAL DEVICE

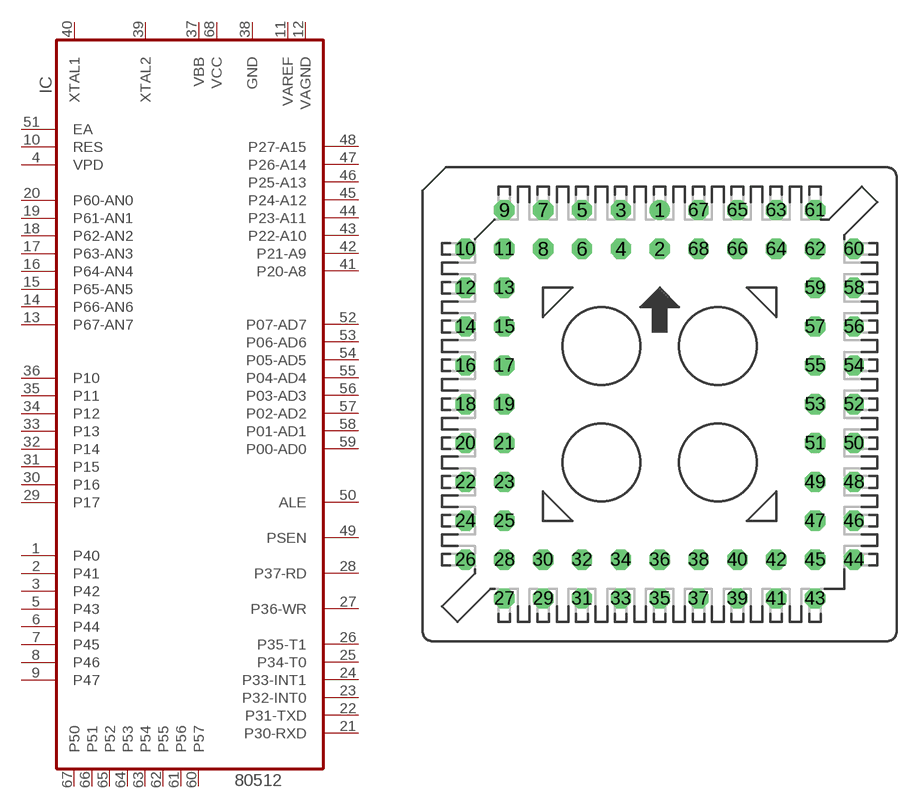
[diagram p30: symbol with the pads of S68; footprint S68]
Designator prefix IC

## 80512 (OC_FARNELL: unknown; OC_NEWARK: unknown)  [S68]
1  P40
2  P41
3  P42
4  VPD  pwr
5  P43
6  P44
7  P45
8  P46
9  P47
10  RES  in
11  VAREF  pwr
12  VAGND  pwr
13  P67-AN7  in
14  P66-AN6  in
15  P65-AN5  in
16  P64-AN4  in
17  P63-AN3  in
18  P62-AN2  in
19  P61-AN1  in
20  P60-AN0  in
21  P30-RXD
22  P31-TXD
23  P32-INT0
24  P33-INT1
25  P34-T0
26  P35-T1
27  P36-WR
28  P37-RD
29  P17
30  P16
31  P15
32  P14
33  P13
34  P12
35  P11
36  P10
37  VBB  pwr
38  GND  pwr
39  XTAL2  in
40  XTAL1  in
41  P20-A8
42  P21-A9
43  P22-A10
44  P23-A11
45  P24-A12
46  P25-A13
47  P26-A14
48  P27-A15
49  PSEN  out
50  ALE  out
51  EA  in
52  P07-AD7
53  P06-AD6
54  P05-AD5
55  P04-AD4
56  P03-AD3
57  P02-AD2
58  P01-AD1
59  P00-AD0
60  P57
61  P56
62  P55
63  P54
64  P53
65  P52
66  P51
67  P50
68  VCC  pwr

## Footprint S68 (pad centres in mm)
PLCC SOCKET
drill 0.813 round: 1 0,12.7
drill 0.813 octagon: 2 0,10.16; 3 -2.54,12.7; 4 -2.54,10.16; 5 -5.08,12.7; 6 -5.08,10.16; 7 -7.62,12.7; 8 -7.62,10.16; 9 -10.16,12.7; 10 -12.7,10.16; 11 -10.16,10.16; 12 -12.7,7.62; 13 -10.16,7.62; 14 -12.7,5.08; 15 -10.16,5.08; 16 -12.7,2.54; 17 -10.16,2.54; 18 -12.7,0; 19 -10.16,0; 20 -12.7,-2.54; 21 -10.16,-2.54; 22 -12.7,-5.08; 23 -10.16,-5.08; 24 -12.7,-7.62; 25 -10.16,-7.62; 26 -12.7,-10.16; 27 -10.16,-12.7; 28 -10.16,-10.16; 29 -7.62,-12.7; 30 -7.62,-10.16; 31 -5.08,-12.7; 32 -5.08,-10.16; 33 -2.54,-12.7; 34 -2.54,-10.16; 35 0,-12.7; 36 0,-10.16; 37 2.54,-12.7; 38 2.54,-10.16; 39 5.08,-12.7; 40 5.08,-10.16; 41 7.62,-12.7; 42 7.62,-10.16; 43 10.16,-12.7; 44 12.7,-10.16; 45 10.16,-10.16; 46 12.7,-7.62; 47 10.16,-7.62; 48 12.7,-5.08; 49 10.16,-5.08; 50 12.7,-2.54; 51 10.16,-2.54; 52 12.7,0; 53 10.16,0; 54 12.7,2.54; 55 10.16,2.54; 56 12.7,5.08; 57 10.16,5.08; 58 12.7,7.62; 59 10.16,7.62; 60 12.7,10.16; 61 10.16,12.7; 62 10.16,10.16; 63 7.62,12.7; 64 7.62,10.16; 65 5.08,12.7; 66 5.08,10.16; 67 2.54,12.7; 68 2.54,10.16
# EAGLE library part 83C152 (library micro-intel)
MICROCOMPUTER/PERIPHERAL DEVICE

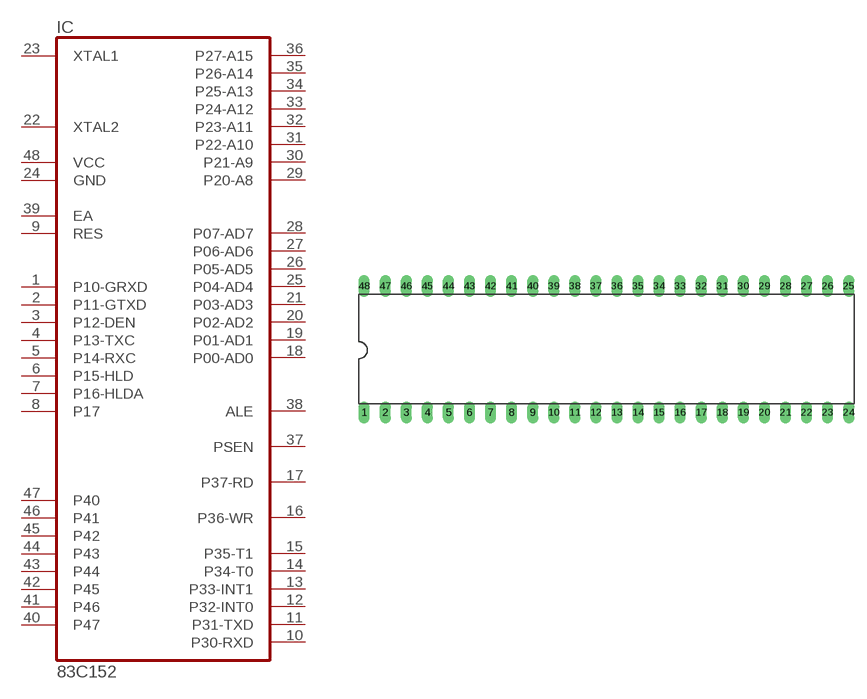
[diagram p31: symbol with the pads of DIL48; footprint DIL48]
Designator prefix IC

## 83C152 (OC_FARNELL: unknown; OC_NEWARK: unknown)  [DIL48]
1  P10-GRXD
2  P11-GTXD
3  P12-DEN
4  P13-TXC
5  P14-RXC
6  P15-HLD
7  P16-HLDA
8  P17
9  RES  in
10  P30-RXD
11  P31-TXD
12  P32-INT0
13  P33-INT1
14  P34-T0
15  P35-T1
16  P36-WR
17  P37-RD
18  P00-AD0
19  P01-AD1
20  P02-AD2
21  P03-AD3
22  XTAL2  in
23  XTAL1  in
24  GND  pwr
25  P04-AD4
26  P05-AD5
27  P06-AD6
28  P07-AD7
29  P20-A8
30  P21-A9
31  P22-A10
32  P23-A11
33  P24-A12
34  P25-A13
35  P26-A14
36  P27-A15
37  PSEN  out
38  ALE  out
39  EA  in
40  P47
41  P46
42  P45
43  P44
44  P43
45  P42
46  P41
47  P40
48  VCC  pwr

## Footprint DIL48 (pad centres in mm)
Dual In Line Package
drill 0.813 long: 1 -29.21,-7.62; 2 -26.67,-7.62; 3 -24.13,-7.62; 4 -21.59,-7.62; 5 -19.05,-7.62; 6 -16.51,-7.62; 7 -13.97,-7.62; 8 -11.43,-7.62; 9 -8.89,-7.62; 10 -6.35,-7.62; 11 -3.81,-7.62; 12 -1.27,-7.62; 13 1.27,-7.62; 14 3.81,-7.62; 15 6.35,-7.62; 16 8.89,-7.62; 17 11.43,-7.62; 18 13.97,-7.62; 19 16.51,-7.62; 20 19.05,-7.62; 21 21.59,-7.62; 22 24.13,-7.62; 23 26.67,-7.62; 24 29.21,-7.62; 25 29.21,7.62; 26 26.67,7.62; 27 24.13,7.62; 28 21.59,7.62; 29 19.05,7.62; 30 16.51,7.62; 31 13.97,7.62; 32 11.43,7.62; 33 8.89,7.62; 34 6.35,7.62; 35 3.81,7.62; 36 1.27,7.62; 37 -1.27,7.62; 38 -3.81,7.62; 39 -6.35,7.62; 40 -8.89,7.62; 41 -11.43,7.62; 42 -13.97,7.62; 43 -16.51,7.62; 44 -19.05,7.62; 45 -21.59,7.62; 46 -24.13,7.62; 47 -26.67,7.62; 48 -29.21,7.62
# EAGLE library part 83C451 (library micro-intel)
MICROCOMPUTER/PERIPHERAL DEVICE

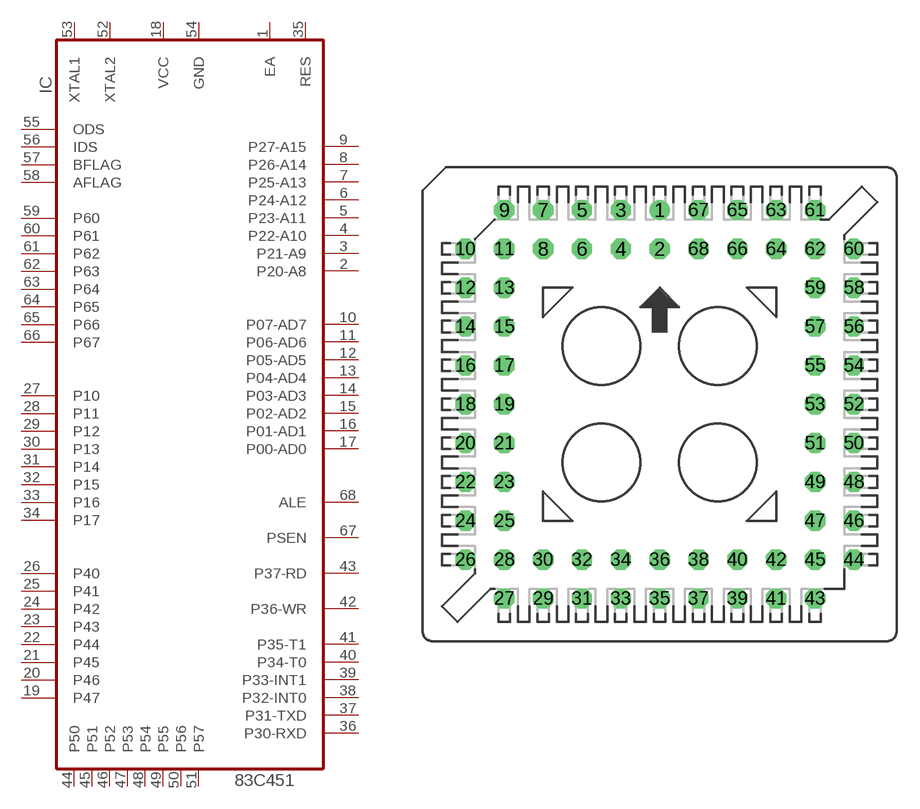
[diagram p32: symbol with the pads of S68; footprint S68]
Designator prefix IC

## 83C451 (OC_FARNELL: unknown; OC_NEWARK: unknown)  [S68]
1  EA  in
2  P20-A8
3  P21-A9
4  P22-A10
5  P23-A11
6  P24-A12
7  P25-A13
8  P26-A14
9  P27-A15
10  P07-AD7
11  P06-AD6
12  P05-AD5
13  P04-AD4
14  P03-AD3
15  P02-AD2
16  P01-AD1
17  P00-AD0
18  VCC  pwr
19  P47
20  P46
21  P45
22  P44
23  P43
24  P42
25  P41
26  P40
27  P10
28  P11
29  P12
30  P13
31  P14
32  P15
33  P16
34  P17
35  RES  in
36  P30-RXD
37  P31-TXD
38  P32-INT0
39  P33-INT1
40  P34-T0
41  P35-T1
42  P36-WR
43  P37-RD
44  P50
45  P51
46  P52
47  P53
48  P54
49  P55
50  P56
51  P57
52  XTAL2  in
53  XTAL1  in
54  GND  pwr
55  ODS
56  IDS
57  BFLAG
58  AFLAG
59  P60
60  P61
61  P62
62  P63
63  P64
64  P65
65  P66
66  P67
67  PSEN  out
68  ALE  out

## Footprint S68 (pad centres in mm)
PLCC SOCKET
drill 0.813 round: 1 0,12.7
drill 0.813 octagon: 2 0,10.16; 3 -2.54,12.7; 4 -2.54,10.16; 5 -5.08,12.7; 6 -5.08,10.16; 7 -7.62,12.7; 8 -7.62,10.16; 9 -10.16,12.7; 10 -12.7,10.16; 11 -10.16,10.16; 12 -12.7,7.62; 13 -10.16,7.62; 14 -12.7,5.08; 15 -10.16,5.08; 16 -12.7,2.54; 17 -10.16,2.54; 18 -12.7,0; 19 -10.16,0; 20 -12.7,-2.54; 21 -10.16,-2.54; 22 -12.7,-5.08; 23 -10.16,-5.08; 24 -12.7,-7.62; 25 -10.16,-7.62; 26 -12.7,-10.16; 27 -10.16,-12.7; 28 -10.16,-10.16; 29 -7.62,-12.7; 30 -7.62,-10.16; 31 -5.08,-12.7; 32 -5.08,-10.16; 33 -2.54,-12.7; 34 -2.54,-10.16; 35 0,-12.7; 36 0,-10.16; 37 2.54,-12.7; 38 2.54,-10.16; 39 5.08,-12.7; 40 5.08,-10.16; 41 7.62,-12.7; 42 7.62,-10.16; 43 10.16,-12.7; 44 12.7,-10.16; 45 10.16,-10.16; 46 12.7,-7.62; 47 10.16,-7.62; 48 12.7,-5.08; 49 10.16,-5.08; 50 12.7,-2.54; 51 10.16,-2.54; 52 12.7,0; 53 10.16,0; 54 12.7,2.54; 55 10.16,2.54; 56 12.7,5.08; 57 10.16,5.08; 58 12.7,7.62; 59 10.16,7.62; 60 12.7,10.16; 61 10.16,12.7; 62 10.16,10.16; 63 7.62,12.7; 64 7.62,10.16; 65 5.08,12.7; 66 5.08,10.16; 67 2.54,12.7; 68 2.54,10.16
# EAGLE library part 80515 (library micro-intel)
MICROCOMPUTER/PERIPHERAL DEVICE

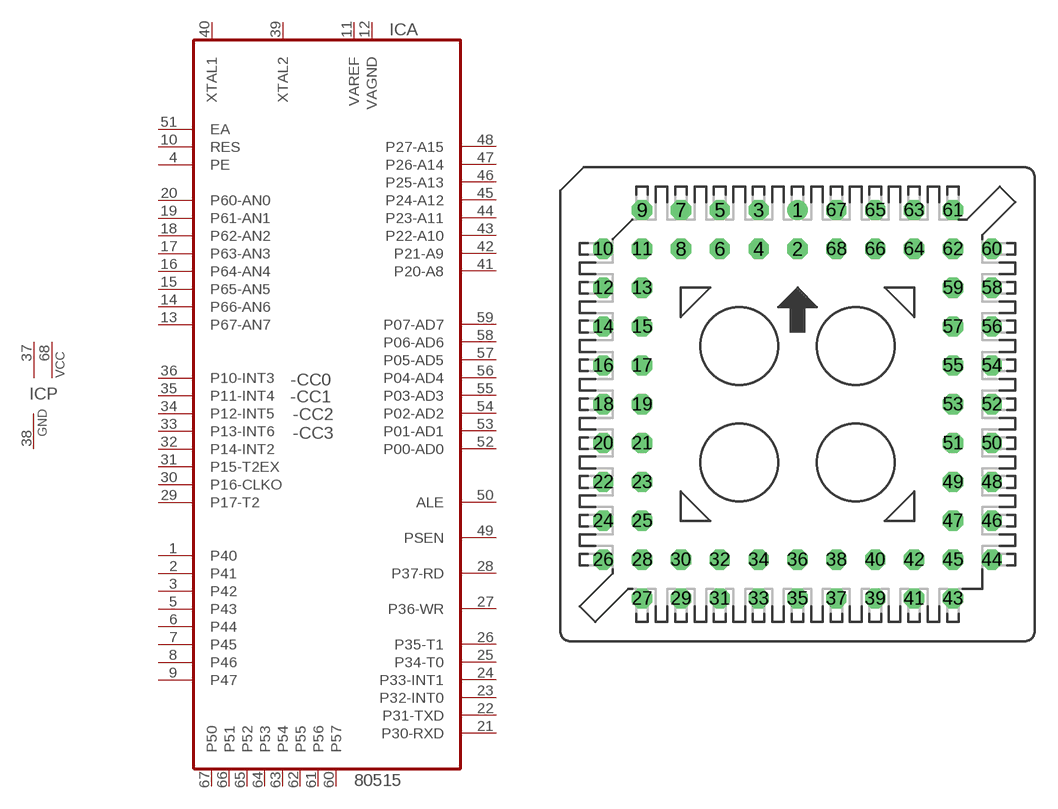
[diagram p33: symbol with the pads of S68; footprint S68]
Designator prefix IC; gates A=80515 P=2VCC1GND

## 80515 (OC_FARNELL: unknown; OC_NEWARK: unknown)  [S68]
1  A:P40
2  A:P41
3  A:P42
4  A:PE  in
5  A:P43
6  A:P44
7  A:P45
8  A:P46
9  A:P47
10  A:RES  in
11  A:VAREF  pwr
12  A:VAGND  pwr
13  A:P67-AN7  in
14  A:P66-AN6  in
15  A:P65-AN5  in
16  A:P64-AN4  in
17  A:P63-AN3  in
18  A:P62-AN2  in
19  A:P61-AN1  in
20  A:P60-AN0  in
21  A:P30-RXD
22  A:P31-TXD
23  A:P32-INT0
24  A:P33-INT1
25  A:P34-T0
26  A:P35-T1
27  A:P36-WR
28  A:P37-RD
29  A:P17-T2
30  A:P16-CLKO
31  A:P15-T2EX
32  A:P14-INT2
33  A:P13-INT6
34  A:P12-INT5
35  A:P11-INT4
36  A:P10-INT3
37  P:VCC  pwr
38  P:GND  pwr
39  A:XTAL2  in
40  A:XTAL1  in
41  A:P20-A8
42  A:P21-A9
43  A:P22-A10
44  A:P23-A11
45  A:P24-A12
46  A:P25-A13
47  A:P26-A14
48  A:P27-A15
49  A:PSEN  out
50  A:ALE  out
51  A:EA  in
52  A:P00-AD0
53  A:P01-AD1
54  A:P02-AD2
55  A:P03-AD3
56  A:P04-AD4
57  A:P05-AD5
58  A:P06-AD6
59  A:P07-AD7
60  A:P57
61  A:P56
62  A:P55
63  A:P54
64  A:P53
65  A:P52
66  A:P51
67  A:P50
68  P:VCC  pwr

## Footprint S68 (pad centres in mm)
PLCC SOCKET
drill 0.813 round: 1 0,12.7
drill 0.813 octagon: 2 0,10.16; 3 -2.54,12.7; 4 -2.54,10.16; 5 -5.08,12.7; 6 -5.08,10.16; 7 -7.62,12.7; 8 -7.62,10.16; 9 -10.16,12.7; 10 -12.7,10.16; 11 -10.16,10.16; 12 -12.7,7.62; 13 -10.16,7.62; 14 -12.7,5.08; 15 -10.16,5.08; 16 -12.7,2.54; 17 -10.16,2.54; 18 -12.7,0; 19 -10.16,0; 20 -12.7,-2.54; 21 -10.16,-2.54; 22 -12.7,-5.08; 23 -10.16,-5.08; 24 -12.7,-7.62; 25 -10.16,-7.62; 26 -12.7,-10.16; 27 -10.16,-12.7; 28 -10.16,-10.16; 29 -7.62,-12.7; 30 -7.62,-10.16; 31 -5.08,-12.7; 32 -5.08,-10.16; 33 -2.54,-12.7; 34 -2.54,-10.16; 35 0,-12.7; 36 0,-10.16; 37 2.54,-12.7; 38 2.54,-10.16; 39 5.08,-12.7; 40 5.08,-10.16; 41 7.62,-12.7; 42 7.62,-10.16; 43 10.16,-12.7; 44 12.7,-10.16; 45 10.16,-10.16; 46 12.7,-7.62; 47 10.16,-7.62; 48 12.7,-5.08; 49 10.16,-5.08; 50 12.7,-2.54; 51 10.16,-2.54; 52 12.7,0; 53 10.16,0; 54 12.7,2.54; 55 10.16,2.54; 56 12.7,5.08; 57 10.16,5.08; 58 12.7,7.62; 59 10.16,7.62; 60 12.7,10.16; 61 10.16,12.7; 62 10.16,10.16; 63 7.62,12.7; 64 7.62,10.16; 65 5.08,12.7; 66 5.08,10.16; 67 2.54,12.7; 68 2.54,10.16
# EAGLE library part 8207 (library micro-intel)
MICROCOMPUTER/PERIPHERAL DEVICE

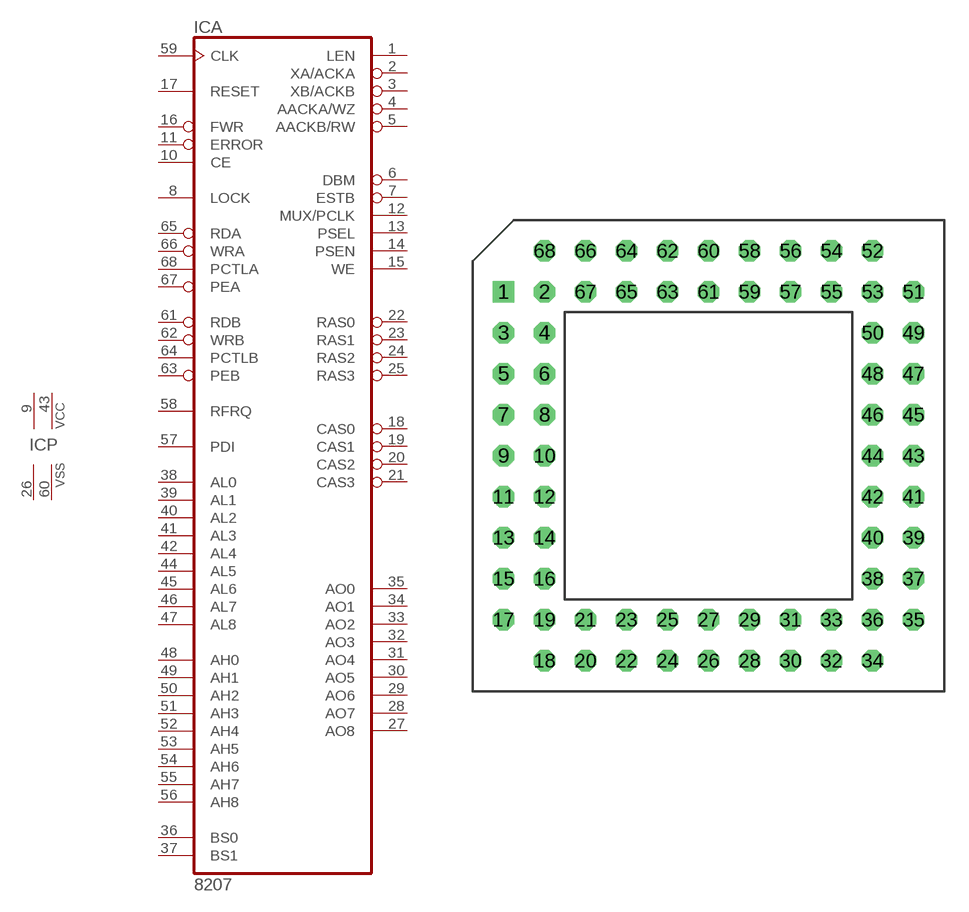
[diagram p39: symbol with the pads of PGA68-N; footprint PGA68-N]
Designator prefix IC; gates A=8207 P=2PWR2VSS

## 8207 (OC_FARNELL: unknown; OC_NEWARK: unknown)  [PGA68-N]
1  A:LEN  out
2  A:XA/ACKA  out
3  A:XB/ACKB  out
4  A:AACKA/WZ  out
5  A:AACKB/RW  out
6  A:DBM  out
7  A:ESTB  out
8  A:LOCK  in
9  P:VCC  pwr
10  A:CE  in
11  A:ERROR  in
12  A:MUX/PCLK  out
13  A:PSEL  out
14  A:PSEN  out
15  A:WE  out
16  A:FWR  in
17  A:RESET  in
18  A:CAS0  out
19  A:CAS1  out
20  A:CAS2  out
21  A:CAS3  out
22  A:RAS0  out
23  A:RAS1  out
24  A:RAS2  out
25  A:RAS3  out
26  P:VSS  pwr
27  A:AO8  out
28  A:AO7  out
29  A:AO6  out
30  A:AO5  out
31  A:AO4  out
32  A:AO3  out
33  A:AO2  out
34  A:AO1  out
35  A:AO0  out
36  A:BS0  in
37  A:BS1  in
38  A:AL0  in
39  A:AL1  in
40  A:AL2  in
41  A:AL3  in
42  A:AL4  in
43  P:VCC  pwr
44  A:AL5  in
45  A:AL6  in
46  A:AL7  in
47  A:AL8  in
48  A:AH0  in
49  A:AH1  in
50  A:AH2  in
51  A:AH3  in
52  A:AH4  in
53  A:AH5  in
54  A:AH6  in
55  A:AH7  in
56  A:AH8  in
57  A:PDI  in
58  A:RFRQ  in
59  A:CLK  in
60  P:VSS  pwr
61  A:RDB  in
62  A:WRB  in
63  A:PEB  in
64  A:PCTLB  in
65  A:RDA  in
66  A:WRA  in
67  A:PEA  in
68  A:PCTLA  in

## Footprint PGA68-N (pad centres in mm)
Pin Grid Array
drill 0.813 square: 1 -12.7,10.16
drill 0.813 octagon: 2 -10.16,10.16; 3 -12.7,7.62; 4 -10.16,7.62; 5 -12.7,5.08; 6 -10.16,5.08; 7 -12.7,2.54; 8 -10.16,2.54; 9 -12.7,0; 10 -10.16,0; 11 -12.7,-2.54; 12 -10.16,-2.54; 13 -12.7,-5.08; 14 -10.16,-5.08; 15 -12.7,-7.62; 16 -10.16,-7.62; 17 -12.7,-10.16; 18 -10.16,-12.7; 19 -10.16,-10.16; 20 -7.62,-12.7; 21 -7.62,-10.16; 22 -5.08,-12.7; 23 -5.08,-10.16; 24 -2.54,-12.7; 25 -2.54,-10.16; 26 0,-12.7; 27 0,-10.16; 28 2.54,-12.7; 29 2.54,-10.16; 30 5.08,-12.7; 31 5.08,-10.16; 32 7.62,-12.7; 33 7.62,-10.16; 34 10.16,-12.7; 35 12.7,-10.16; 36 10.16,-10.16; 37 12.7,-7.62; 38 10.16,-7.62; 39 12.7,-5.08; 40 10.16,-5.08; 41 12.7,-2.54; 42 10.16,-2.54; 43 12.7,0; 44 10.16,0; 45 12.7,2.54; 46 10.16,2.54; 47 12.7,5.08; 48 10.16,5.08; 49 12.7,7.62; 50 10.16,7.62; 51 12.7,10.16; 52 10.16,12.7; 53 10.16,10.16; 54 7.62,12.7; 55 7.62,10.16; 56 5.08,12.7; 57 5.08,10.16; 58 2.54,12.7; 59 2.54,10.16; 60 0,12.7; 61 0,10.16; 62 -2.54,12.7; 63 -2.54,10.16; 64 -5.08,12.7; 65 -5.08,10.16; 66 -7.62,12.7; 67 -7.62,10.16; 68 -10.16,12.7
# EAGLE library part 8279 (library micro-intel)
MICROCOMPUTER/PERIPHERAL DEVICE

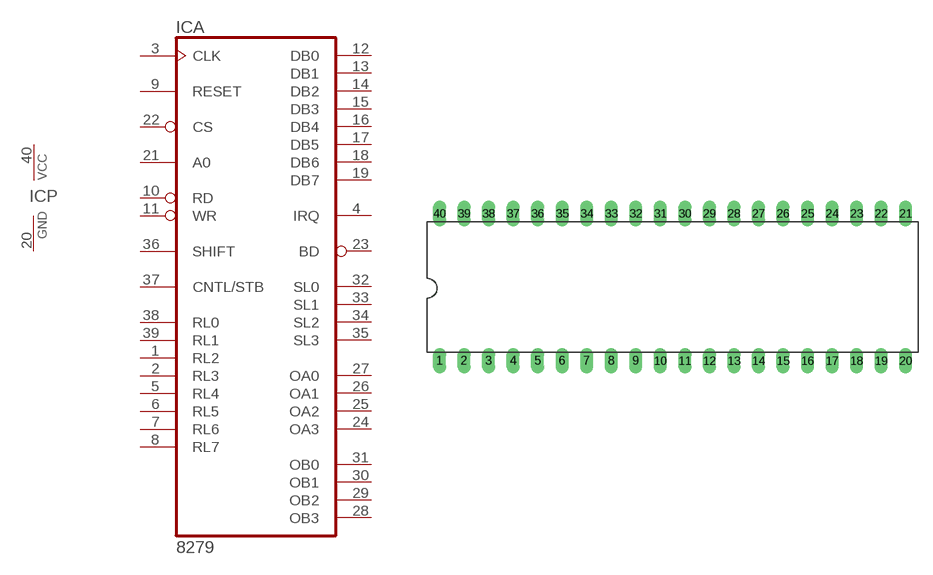
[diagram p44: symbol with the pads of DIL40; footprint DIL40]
Designator prefix IC; gates A=8279 P=PWRN

## 8279 (OC_FARNELL: unknown; OC_NEWARK: unknown)  [DIL40]
1  A:RL2  in
2  A:RL3  in
3  A:CLK  in
4  A:IRQ  out
5  A:RL4  in
6  A:RL5  in
7  A:RL6  in
8  A:RL7  in
9  A:RESET  in
10  A:RD  in
11  A:WR  in
12  A:DB0
13  A:DB1
14  A:DB2
15  A:DB3
16  A:DB4
17  A:DB5
18  A:DB6
19  A:DB7
20  P:GND  pwr
21  A:A0  in
22  A:CS  in
23  A:BD  out
24  A:OA3  out
25  A:OA2  out
26  A:OA1  out
27  A:OA0  out
28  A:OB3  out
29  A:OB2  out
30  A:OB1  out
31  A:OB0  out
32  A:SL0  out
33  A:SL1  out
34  A:SL2  out
35  A:SL3  out
36  A:SHIFT  in
37  A:CNTL/STB  in
38  A:RL0  in
39  A:RL1  in
40  P:VCC  pwr

## Footprint DIL40 (pad centres in mm)
Dual In Line Package
drill 0.813 long: 1 -24.13,-7.62; 2 -21.59,-7.62; 3 -19.05,-7.62; 4 -16.51,-7.62; 5 -13.97,-7.62; 6 -11.43,-7.62; 7 -8.89,-7.62; 8 -6.35,-7.62; 9 -3.81,-7.62; 10 -1.27,-7.62; 11 1.27,-7.62; 12 3.81,-7.62; 13 6.35,-7.62; 14 8.89,-7.62; 15 11.43,-7.62; 16 13.97,-7.62; 17 16.51,-7.62; 18 19.05,-7.62; 19 21.59,-7.62; 20 24.13,-7.62; 21 24.13,7.62; 22 21.59,7.62; 23 19.05,7.62; 24 16.51,7.62; 25 13.97,7.62; 26 11.43,7.62; 27 8.89,7.62; 28 6.35,7.62; 29 3.81,7.62; 30 1.27,7.62; 31 -1.27,7.62; 32 -3.81,7.62; 33 -6.35,7.62; 34 -8.89,7.62; 35 -11.43,7.62; 36 -13.97,7.62; 37 -16.51,7.62; 38 -19.05,7.62; 39 -21.59,7.62; 40 -24.13,7.62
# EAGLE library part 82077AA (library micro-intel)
MICROCOMPUTER/PERIPHERAL DEVICE

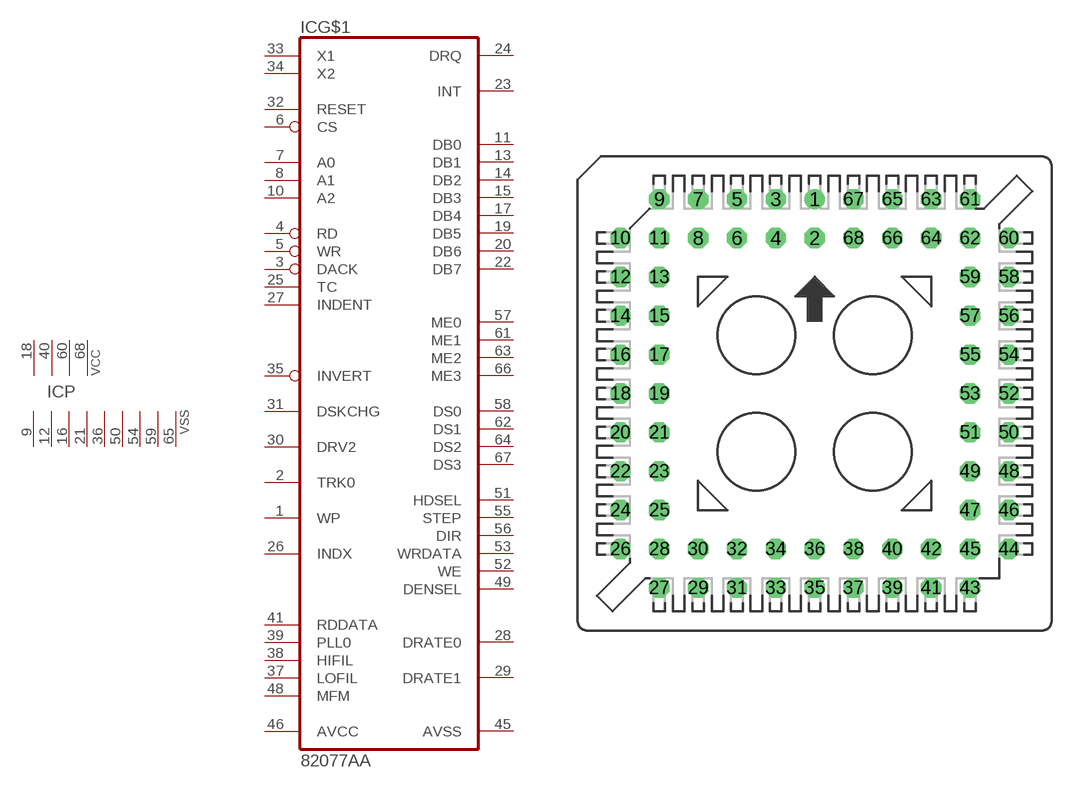
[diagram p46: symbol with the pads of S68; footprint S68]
Designator prefix IC; gates G$1=82077AA P=4PWR9VSS

## 82077AA (OC_FARNELL: unknown; OC_NEWARK: unknown)  [S68]
1  G$1:WP  in
2  G$1:TRK0  in
3  G$1:DACK  in
4  G$1:RD  in
5  G$1:WR  in
6  G$1:CS  in
7  G$1:A0  in
8  G$1:A1  in
9  P:VSS  pwr
10  G$1:A2  in
11  G$1:DB0
12  P:VSS  pwr
13  G$1:DB1
14  G$1:DB2
15  G$1:DB3
16  P:VSS  pwr
17  G$1:DB4
18  P:VCC  pwr
19  G$1:DB5
20  G$1:DB6
21  P:VSS  pwr
22  G$1:DB7
23  G$1:INT  out
24  G$1:DRQ  out
25  G$1:TC  in
26  G$1:INDX  in
27  G$1:INDENT  in
28  G$1:DRATE0  out
29  G$1:DRATE1  out
30  G$1:DRV2  in
31  G$1:DSKCHG  in
32  G$1:RESET  in
33  G$1:X1  in
34  G$1:X2  in
35  G$1:INVERT  in
36  P:VSS  pwr
37  G$1:LOFIL
38  G$1:HIFIL
39  G$1:PLL0  in
40  P:VCC  pwr
41  G$1:RDDATA  in
45  G$1:AVSS  pwr
46  G$1:AVCC  pwr
48  G$1:MFM
49  G$1:DENSEL  out
50  P:VSS  pwr
51  G$1:HDSEL  out
52  G$1:WE  out
53  G$1:WRDATA  out
54  P:VSS  pwr
55  G$1:STEP  out
56  G$1:DIR  out
57  G$1:ME0  out
58  G$1:DS0  out
59  P:VSS  pwr
60  P:VCC  pwr
61  G$1:ME1  out
62  G$1:DS1  out
63  G$1:ME2  out
64  G$1:DS2  out
65  P:VSS  pwr
66  G$1:ME3  out
67  G$1:DS3  out
68  P:VCC  pwr

## Footprint S68 (pad centres in mm)
PLCC SOCKET
drill 0.813 round: 1 0,12.7
drill 0.813 octagon: 2 0,10.16; 3 -2.54,12.7; 4 -2.54,10.16; 5 -5.08,12.7; 6 -5.08,10.16; 7 -7.62,12.7; 8 -7.62,10.16; 9 -10.16,12.7; 10 -12.7,10.16; 11 -10.16,10.16; 12 -12.7,7.62; 13 -10.16,7.62; 14 -12.7,5.08; 15 -10.16,5.08; 16 -12.7,2.54; 17 -10.16,2.54; 18 -12.7,0; 19 -10.16,0; 20 -12.7,-2.54; 21 -10.16,-2.54; 22 -12.7,-5.08; 23 -10.16,-5.08; 24 -12.7,-7.62; 25 -10.16,-7.62; 26 -12.7,-10.16; 27 -10.16,-12.7; 28 -10.16,-10.16; 29 -7.62,-12.7; 30 -7.62,-10.16; 31 -5.08,-12.7; 32 -5.08,-10.16; 33 -2.54,-12.7; 34 -2.54,-10.16; 35 0,-12.7; 36 0,-10.16; 37 2.54,-12.7; 38 2.54,-10.16; 39 5.08,-12.7; 40 5.08,-10.16; 41 7.62,-12.7; 42 7.62,-10.16; 43 10.16,-12.7; 44 12.7,-10.16; 45 10.16,-10.16; 46 12.7,-7.62; 47 10.16,-7.62; 48 12.7,-5.08; 49 10.16,-5.08; 50 12.7,-2.54; 51 10.16,-2.54; 52 12.7,0; 53 10.16,0; 54 12.7,2.54; 55 10.16,2.54; 56 12.7,5.08; 57 10.16,5.08; 58 12.7,7.62; 59 10.16,7.62; 60 12.7,10.16; 61 10.16,12.7; 62 10.16,10.16; 63 7.62,12.7; 64 7.62,10.16; 65 5.08,12.7; 66 5.08,10.16; 67 2.54,12.7; 68 2.54,10.16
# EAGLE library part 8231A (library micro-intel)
MICROCOMPUTER/PERIPHERAL DEVICE

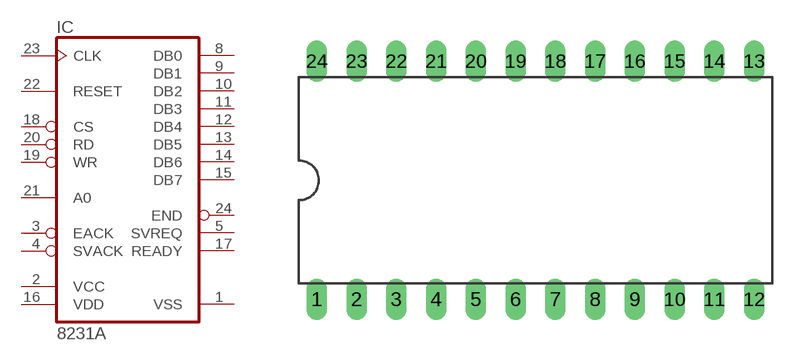
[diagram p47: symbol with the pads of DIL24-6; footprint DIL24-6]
Designator prefix IC

## 8231A (OC_FARNELL: unknown; OC_NEWARK: unknown)  [DIL24-6]
1  VSS  pwr
2  VCC  pwr
3  EACK  in
4  SVACK  in
5  SVREQ  out
8  DB0
9  DB1
10  DB2
11  DB3
12  DB4
13  DB5
14  DB6
15  DB7
16  VDD  pwr
17  READY  out
18  CS  in
19  WR  in
20  RD  in
21  A0  in
22  RESET  in
23  CLK  in
24  END  out

## Footprint DIL24-6 (pad centres in mm)
Dual In Line Package 0.6 inch
drill 0.813 long: 1 -13.97,-7.62; 2 -11.43,-7.62; 3 -8.89,-7.62; 4 -6.35,-7.62; 5 -3.81,-7.62; 6 -1.27,-7.62; 7 1.27,-7.62; 8 3.81,-7.62; 9 6.35,-7.62; 10 8.89,-7.62; 11 11.43,-7.62; 12 13.97,-7.62; 13 13.97,7.62; 14 11.43,7.62; 15 8.89,7.62; 16 6.35,7.62; 17 3.81,7.62; 18 1.27,7.62; 19 -1.27,7.62; 20 -3.81,7.62; 21 -6.35,7.62; 22 -8.89,7.62; 23 -11.43,7.62; 24 -13.97,7.62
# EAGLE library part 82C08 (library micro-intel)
MICROCOMPUTER/PERIPHERAL DEVICE

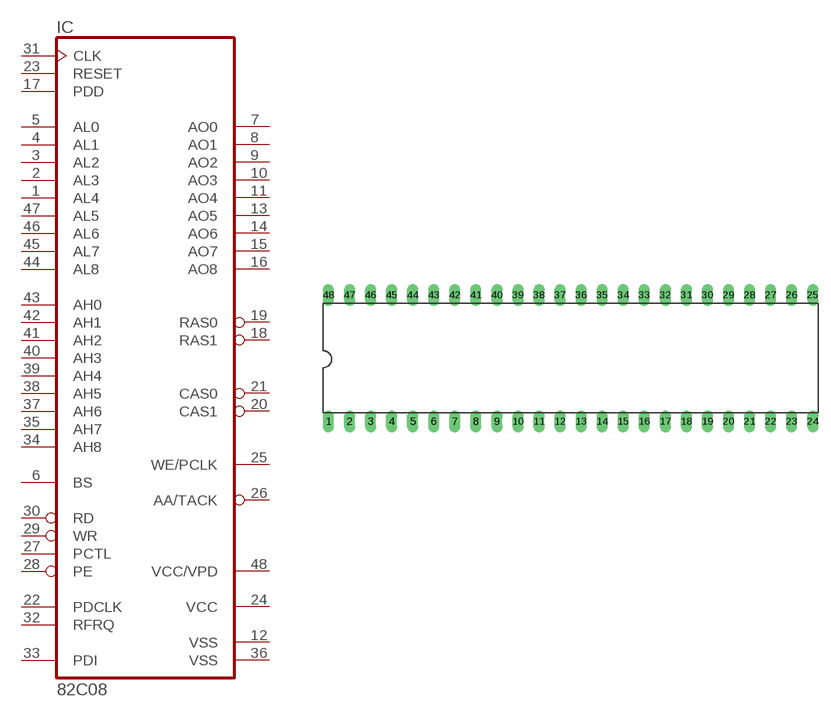
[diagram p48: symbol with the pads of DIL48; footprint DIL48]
Designator prefix IC

## 82C08 (OC_FARNELL: unknown; OC_NEWARK: unknown)  [DIL48]
1  AL4  in
2  AL3  in
3  AL2  in
4  AL1  in
5  AL0  in
6  BS  in
7  AO0  out
8  AO1  out
9  AO2  out
10  AO3  out
11  AO4  out
12  VSS  pwr
13  AO5  out
14  AO6  out
15  AO7  out
16  AO8  out
17  PDD  in
18  RAS1  out
19  RAS0  out
20  CAS1  out
21  CAS0  out
22  PDCLK  in
23  RESET  in
24  VCC  pwr
25  WE/PCLK  out
26  AA/TACK  out
27  PCTL  in
28  PE  in
29  WR  in
30  RD  in
31  CLK  in
32  RFRQ  in
33  PDI  in
34  AH8  in
35  AH7  in
36  VSS  pwr
37  AH6  in
38  AH5  in
39  AH4  in
40  AH3  in
41  AH2  in
42  AH1  in
43  AH0  in
44  AL8  in
45  AL7  in
46  AL6  in
47  AL5  in
48  VCC/VPD  pwr

## Footprint DIL48 (pad centres in mm)
Dual In Line Package
drill 0.813 long: 1 -29.21,-7.62; 2 -26.67,-7.62; 3 -24.13,-7.62; 4 -21.59,-7.62; 5 -19.05,-7.62; 6 -16.51,-7.62; 7 -13.97,-7.62; 8 -11.43,-7.62; 9 -8.89,-7.62; 10 -6.35,-7.62; 11 -3.81,-7.62; 12 -1.27,-7.62; 13 1.27,-7.62; 14 3.81,-7.62; 15 6.35,-7.62; 16 8.89,-7.62; 17 11.43,-7.62; 18 13.97,-7.62; 19 16.51,-7.62; 20 19.05,-7.62; 21 21.59,-7.62; 22 24.13,-7.62; 23 26.67,-7.62; 24 29.21,-7.62; 25 29.21,7.62; 26 26.67,7.62; 27 24.13,7.62; 28 21.59,7.62; 29 19.05,7.62; 30 16.51,7.62; 31 13.97,7.62; 32 11.43,7.62; 33 8.89,7.62; 34 6.35,7.62; 35 3.81,7.62; 36 1.27,7.62; 37 -1.27,7.62; 38 -3.81,7.62; 39 -6.35,7.62; 40 -8.89,7.62; 41 -11.43,7.62; 42 -13.97,7.62; 43 -16.51,7.62; 44 -19.05,7.62; 45 -21.59,7.62; 46 -24.13,7.62; 47 -26.67,7.62; 48 -29.21,7.62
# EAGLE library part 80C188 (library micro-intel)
MICROCOMPUTER/PERIPHERAL DEVICE

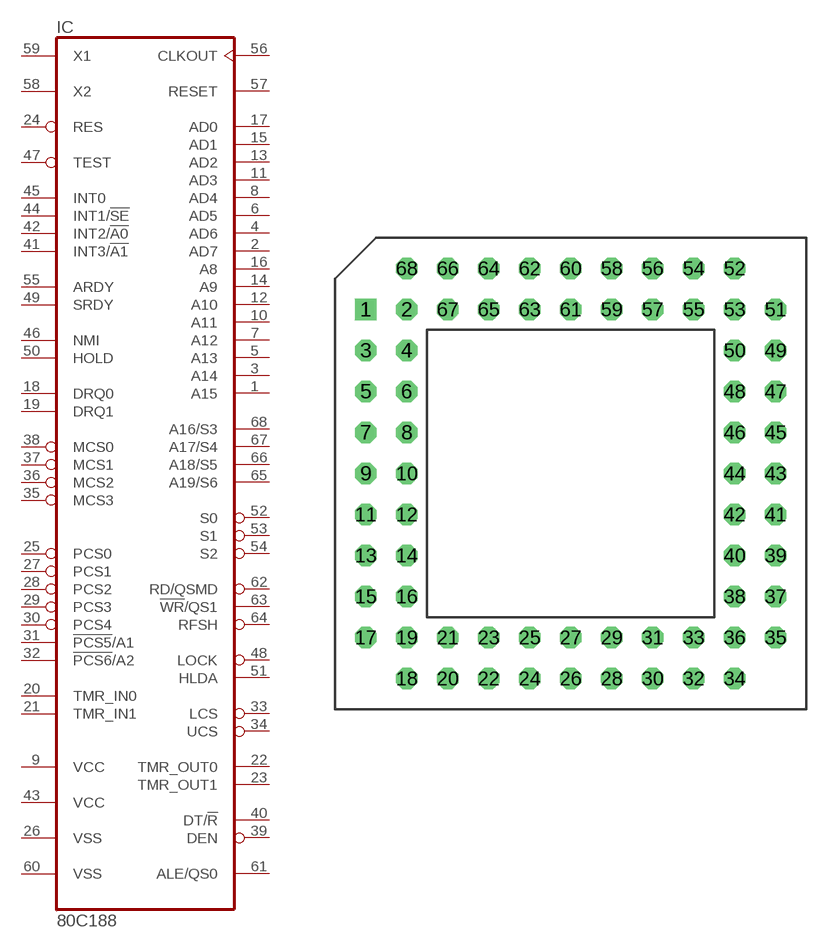
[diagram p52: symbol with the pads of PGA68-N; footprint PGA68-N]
Designator prefix IC

## 80C188 (OC_FARNELL: unknown; OC_NEWARK: unknown)  [PGA68-N]
1  A15  out
2  AD7
3  A14  out
4  AD6
5  A13  out
6  AD5
7  A12  out
8  AD4
9  VCC  pwr
10  A11  out
11  AD3
12  A10  out
13  AD2
14  A9  out
15  AD1
16  A8  out
17  AD0
18  DRQ0  in
19  DRQ1  in
20  TMR_IN0  in
21  TMR_IN1  in
22  TMR_OUT0  out
23  TMR_OUT1  out
24  RES  in
25  PCS0  out
26  VSS  pwr
27  PCS1  out
28  PCS2  out
29  PCS3  out
30  PCS4  out
31  !PCS5!/A1  out
32  !PCS6!/A2  out
33  LCS
34  UCS
35  MCS3  out
36  MCS2  out
37  MCS1  out
38  MCS0  out
39  DEN  out
40  DT/!R  out
41  INT3/!A1
42  INT2/!A0
43  VCC  pwr
44  INT1/!SE  in
45  INT0  in
46  NMI  in
47  TEST
48  LOCK  out
49  SRDY  in
50  HOLD  in
51  HLDA  out
52  S0  out
53  S1  out
54  S2  out
55  ARDY  in
56  CLKOUT  out
57  RESET  out
58  X2  out
59  X1  in
60  VSS  pwr
61  ALE/QS0  out
62  RD/QSMD
63  !WR!/QS1  out
64  RFSH  out
65  A19/S6  out
66  A18/S5  out
67  A17/S4  out
68  A16/S3  out

## Footprint PGA68-N (pad centres in mm)
Pin Grid Array
drill 0.813 square: 1 -12.7,10.16
drill 0.813 octagon: 2 -10.16,10.16; 3 -12.7,7.62; 4 -10.16,7.62; 5 -12.7,5.08; 6 -10.16,5.08; 7 -12.7,2.54; 8 -10.16,2.54; 9 -12.7,0; 10 -10.16,0; 11 -12.7,-2.54; 12 -10.16,-2.54; 13 -12.7,-5.08; 14 -10.16,-5.08; 15 -12.7,-7.62; 16 -10.16,-7.62; 17 -12.7,-10.16; 18 -10.16,-12.7; 19 -10.16,-10.16; 20 -7.62,-12.7; 21 -7.62,-10.16; 22 -5.08,-12.7; 23 -5.08,-10.16; 24 -2.54,-12.7; 25 -2.54,-10.16; 26 0,-12.7; 27 0,-10.16; 28 2.54,-12.7; 29 2.54,-10.16; 30 5.08,-12.7; 31 5.08,-10.16; 32 7.62,-12.7; 33 7.62,-10.16; 34 10.16,-12.7; 35 12.7,-10.16; 36 10.16,-10.16; 37 12.7,-7.62; 38 10.16,-7.62; 39 12.7,-5.08; 40 10.16,-5.08; 41 12.7,-2.54; 42 10.16,-2.54; 43 12.7,0; 44 10.16,0; 45 12.7,2.54; 46 10.16,2.54; 47 12.7,5.08; 48 10.16,5.08; 49 12.7,7.62; 50 10.16,7.62; 51 12.7,10.16; 52 10.16,12.7; 53 10.16,10.16; 54 7.62,12.7; 55 7.62,10.16; 56 5.08,12.7; 57 5.08,10.16; 58 2.54,12.7; 59 2.54,10.16; 60 0,12.7; 61 0,10.16; 62 -2.54,12.7; 63 -2.54,10.16; 64 -5.08,12.7; 65 -5.08,10.16; 66 -7.62,12.7; 67 -7.62,10.16; 68 -10.16,12.7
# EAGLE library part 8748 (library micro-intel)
MICROCOMPUTER/PERIPHERAL DEVICE

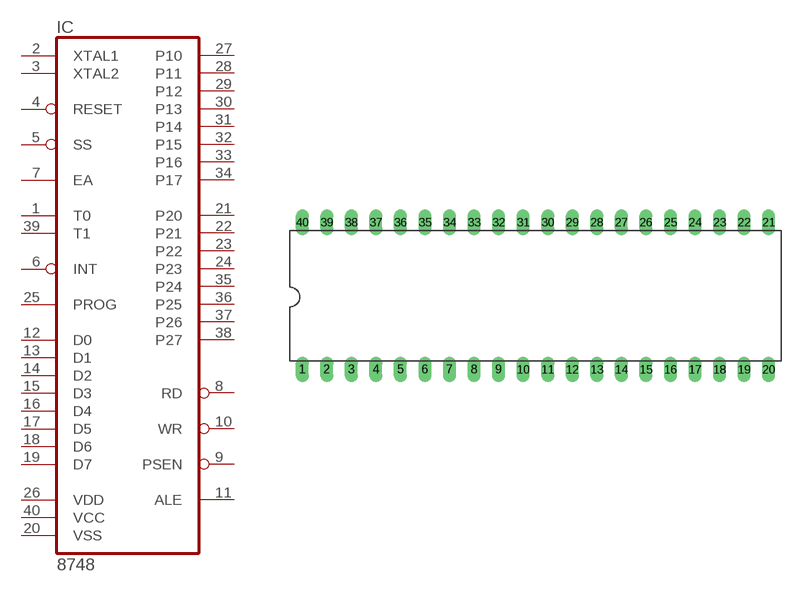
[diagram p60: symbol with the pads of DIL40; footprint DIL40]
Designator prefix IC

## 8748 (OC_FARNELL: unknown; OC_NEWARK: unknown)  [DIL40]
1  T0  in
2  XTAL1  in
3  XTAL2  out
4  RESET  in
5  SS  in
6  INT  in
7  EA  in
8  RD  out
9  PSEN  out
10  WR  out
11  ALE  out
12  D0
13  D1
14  D2
15  D3
16  D4
17  D5
18  D6
19  D7
20  VSS  pwr
21  P20
22  P21
23  P22
24  P23
25  PROG  in
26  VDD  pwr
27  P10
28  P11
29  P12
30  P13
31  P14
32  P15
33  P16
34  P17
35  P24
36  P25
37  P26
38  P27
39  T1  in
40  VCC  pwr

## Footprint DIL40 (pad centres in mm)
Dual In Line Package
drill 0.813 long: 1 -24.13,-7.62; 2 -21.59,-7.62; 3 -19.05,-7.62; 4 -16.51,-7.62; 5 -13.97,-7.62; 6 -11.43,-7.62; 7 -8.89,-7.62; 8 -6.35,-7.62; 9 -3.81,-7.62; 10 -1.27,-7.62; 11 1.27,-7.62; 12 3.81,-7.62; 13 6.35,-7.62; 14 8.89,-7.62; 15 11.43,-7.62; 16 13.97,-7.62; 17 16.51,-7.62; 18 19.05,-7.62; 19 21.59,-7.62; 20 24.13,-7.62; 21 24.13,7.62; 22 21.59,7.62; 23 19.05,7.62; 24 16.51,7.62; 25 13.97,7.62; 26 11.43,7.62; 27 8.89,7.62; 28 6.35,7.62; 29 3.81,7.62; 30 1.27,7.62; 31 -1.27,7.62; 32 -3.81,7.62; 33 -6.35,7.62; 34 -8.89,7.62; 35 -11.43,7.62; 36 -13.97,7.62; 37 -16.51,7.62; 38 -19.05,7.62; 39 -21.59,7.62; 40 -24.13,7.62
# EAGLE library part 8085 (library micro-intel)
MICROCOMPUTER/PERIPHERAL DEVICE

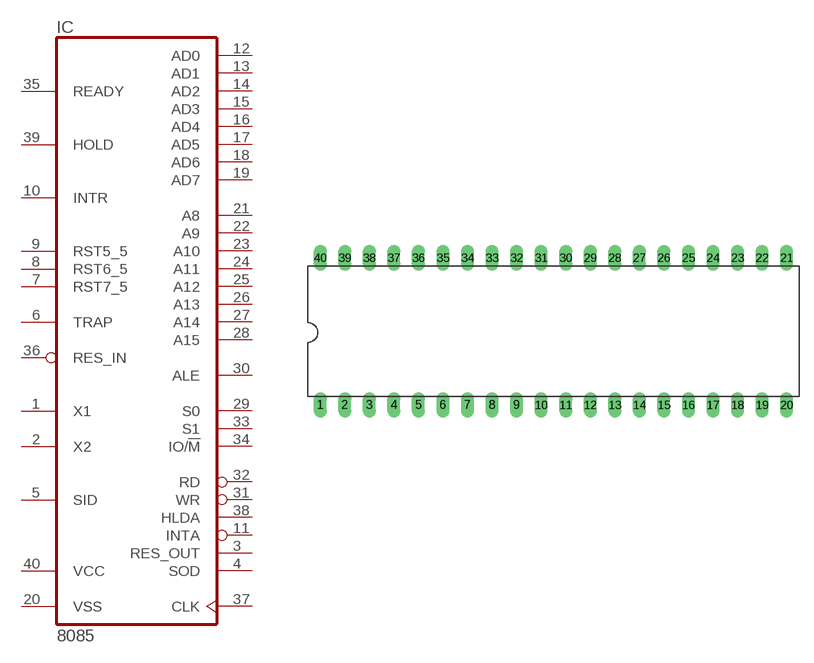
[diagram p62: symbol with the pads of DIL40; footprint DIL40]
Designator prefix IC

## 8085 (OC_FARNELL: unknown; OC_NEWARK: unknown)  [DIL40]
1  X1  in
2  X2  in
3  RES_OUT  out
4  SOD  out
5  SID  in
6  TRAP  in
7  RST7_5  in
8  RST6_5  in
9  RST5_5  in
10  INTR  in
11  INTA  out
12  AD0
13  AD1
14  AD2
15  AD3
16  AD4
17  AD5
18  AD6
19  AD7
20  VSS  pwr
21  A8  out
22  A9  out
23  A10  out
24  A11  out
25  A12  out
26  A13  out
27  A14  out
28  A15  out
29  S0  out
30  ALE  out
31  WR  out
32  RD  out
33  S1  out
34  IO/!M  out
35  READY  in
36  RES_IN  in
37  CLK  out
38  HLDA  out
39  HOLD  in
40  VCC  pwr

## Footprint DIL40 (pad centres in mm)
Dual In Line Package
drill 0.813 long: 1 -24.13,-7.62; 2 -21.59,-7.62; 3 -19.05,-7.62; 4 -16.51,-7.62; 5 -13.97,-7.62; 6 -11.43,-7.62; 7 -8.89,-7.62; 8 -6.35,-7.62; 9 -3.81,-7.62; 10 -1.27,-7.62; 11 1.27,-7.62; 12 3.81,-7.62; 13 6.35,-7.62; 14 8.89,-7.62; 15 11.43,-7.62; 16 13.97,-7.62; 17 16.51,-7.62; 18 19.05,-7.62; 19 21.59,-7.62; 20 24.13,-7.62; 21 24.13,7.62; 22 21.59,7.62; 23 19.05,7.62; 24 16.51,7.62; 25 13.97,7.62; 26 11.43,7.62; 27 8.89,7.62; 28 6.35,7.62; 29 3.81,7.62; 30 1.27,7.62; 31 -1.27,7.62; 32 -3.81,7.62; 33 -6.35,7.62; 34 -8.89,7.62; 35 -11.43,7.62; 36 -13.97,7.62; 37 -16.51,7.62; 38 -19.05,7.62; 39 -21.59,7.62; 40 -24.13,7.62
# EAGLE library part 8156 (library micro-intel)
MICROCOMPUTER/PERIPHERAL DEVICE

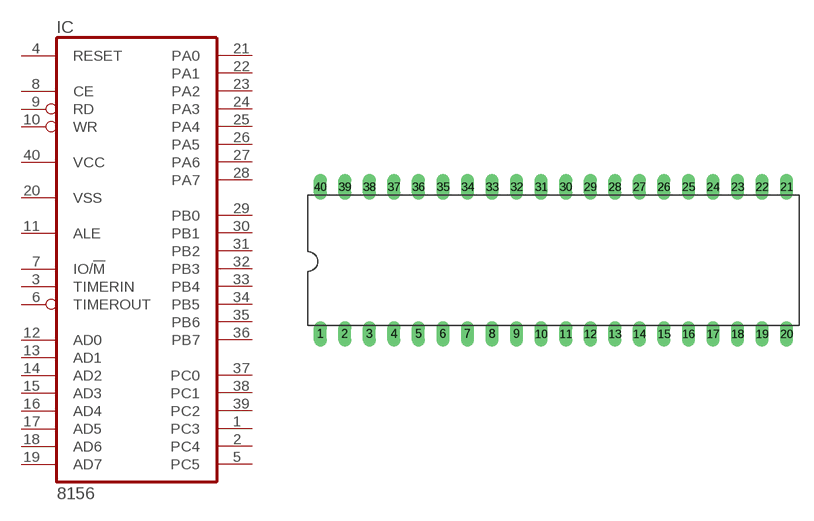
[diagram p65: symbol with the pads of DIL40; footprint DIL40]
Designator prefix IC

## 8156 (OC_FARNELL: unknown; OC_NEWARK: unknown)  [DIL40]
1  PC3
2  PC4
3  TIMERIN  in
4  RESET  in
5  PC5
6  TIMEROUT  out
7  IO/!M  in
8  CE  in
9  RD  in
10  WR  in
11  ALE  in
12  AD0
13  AD1
14  AD2
15  AD3
16  AD4
17  AD5
18  AD6
19  AD7
20  VSS  pwr
21  PA0
22  PA1
23  PA2
24  PA3
25  PA4
26  PA5
27  PA6
28  PA7
29  PB0
30  PB1
31  PB2
32  PB3
33  PB4
34  PB5
35  PB6
36  PB7
37  PC0
38  PC1
39  PC2
40  VCC  pwr

## Footprint DIL40 (pad centres in mm)
Dual In Line Package
drill 0.813 long: 1 -24.13,-7.62; 2 -21.59,-7.62; 3 -19.05,-7.62; 4 -16.51,-7.62; 5 -13.97,-7.62; 6 -11.43,-7.62; 7 -8.89,-7.62; 8 -6.35,-7.62; 9 -3.81,-7.62; 10 -1.27,-7.62; 11 1.27,-7.62; 12 3.81,-7.62; 13 6.35,-7.62; 14 8.89,-7.62; 15 11.43,-7.62; 16 13.97,-7.62; 17 16.51,-7.62; 18 19.05,-7.62; 19 21.59,-7.62; 20 24.13,-7.62; 21 24.13,7.62; 22 21.59,7.62; 23 19.05,7.62; 24 16.51,7.62; 25 13.97,7.62; 26 11.43,7.62; 27 8.89,7.62; 28 6.35,7.62; 29 3.81,7.62; 30 1.27,7.62; 31 -1.27,7.62; 32 -3.81,7.62; 33 -6.35,7.62; 34 -8.89,7.62; 35 -11.43,7.62; 36 -13.97,7.62; 37 -16.51,7.62; 38 -19.05,7.62; 39 -21.59,7.62; 40 -24.13,7.62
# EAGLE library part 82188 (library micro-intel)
MICROCOMPUTER/PERIPHERAL DEVICE

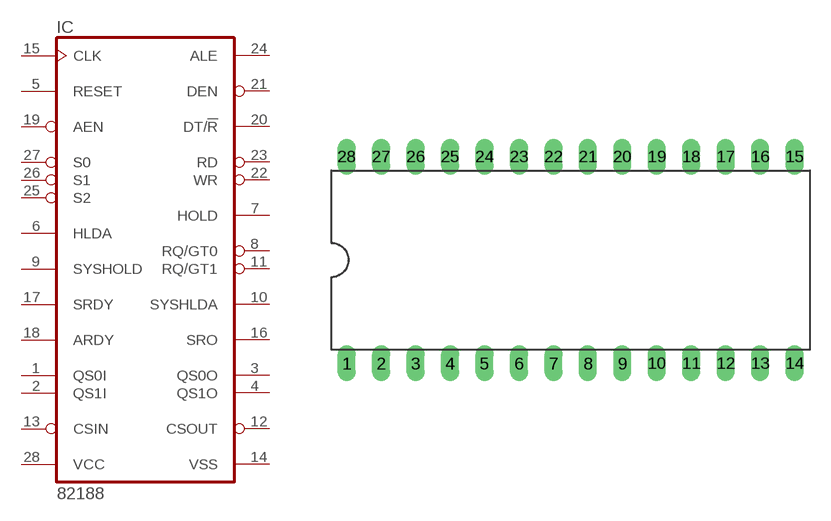
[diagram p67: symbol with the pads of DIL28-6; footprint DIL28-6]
Designator prefix IC

## 82188 (OC_FARNELL: unknown; OC_NEWARK: unknown)  [DIL28-6]
1  QS0I  in
2  QS1I  in
3  QS0O  out
4  QS1O  out
5  RESET  in
6  HLDA  in
7  HOLD  out
8  RQ/GT0
9  SYSHOLD  in
10  SYSHLDA  out
11  RQ/GT1
12  CSOUT  out
13  CSIN  in
14  VSS  pwr
15  CLK  in
16  SRO  out
17  SRDY  in
18  ARDY  in
19  AEN  in
20  DT/!R  out
21  DEN  out
22  WR  out
23  RD  out
24  ALE  out
25  S2  in
26  S1  in
27  S0  in
28  VCC  pwr

## Footprint DIL28-6 (pad centres in mm)
Dual In Line Package 0.6 inch
drill 0.813 long: 1 -16.51,-7.62; 2 -13.97,-7.62; 3 -11.43,-7.62; 4 -8.89,-7.62; 5 -6.35,-7.62; 6 -3.81,-7.62; 7 -1.27,-7.62; 8 1.27,-7.62; 9 3.81,-7.62; 10 6.35,-7.62; 11 8.89,-7.62; 12 11.43,-7.62; 13 13.97,-7.62; 14 16.51,-7.62; 15 16.51,7.62; 16 13.97,7.62; 17 11.43,7.62; 18 8.89,7.62; 19 6.35,7.62; 20 3.81,7.62; 21 1.27,7.62; 22 -1.27,7.62; 23 -3.81,7.62; 24 -6.35,7.62; 25 -8.89,7.62; 26 -11.43,7.62; 27 -13.97,7.62; 28 -16.51,7.62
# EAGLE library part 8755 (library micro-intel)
MICROCOMPUTER/PERIPHERAL DEVICE

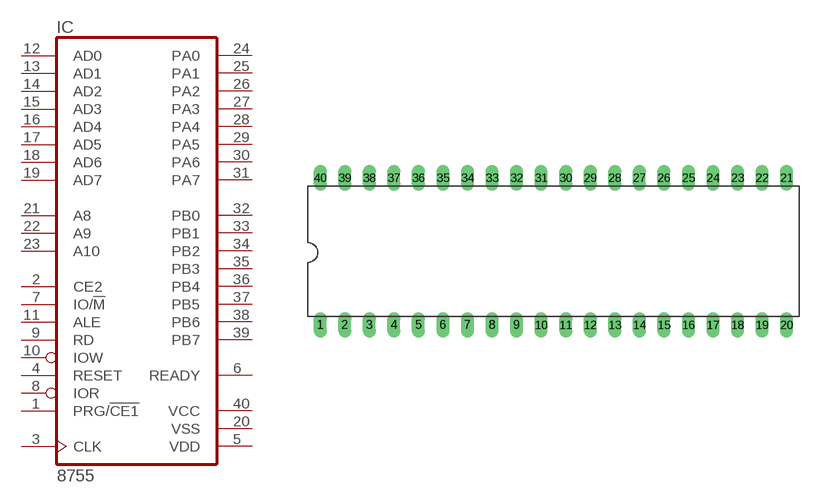
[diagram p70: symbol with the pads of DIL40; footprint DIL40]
Designator prefix IC

## 8755 (OC_FARNELL: unknown; OC_NEWARK: unknown)  [DIL40]
1  PRG/!CE1  in
2  CE2  in
3  CLK  in
4  RESET  in
5  VDD  pwr
6  READY  out
7  IO/!M  in
8  IOR  in
9  RD  in
10  IOW  in
11  ALE  in
12  AD0
13  AD1
14  AD2
15  AD3
16  AD4
17  AD5
18  AD6
19  AD7
20  VSS  pwr
21  A8
22  A9
23  A10
24  PA0
25  PA1
26  PA2
27  PA3
28  PA4
29  PA5
30  PA6
31  PA7
32  PB0
33  PB1
34  PB2
35  PB3
36  PB4
37  PB5
38  PB6
39  PB7
40  VCC  pwr

## Footprint DIL40 (pad centres in mm)
Dual In Line Package
drill 0.813 long: 1 -24.13,-7.62; 2 -21.59,-7.62; 3 -19.05,-7.62; 4 -16.51,-7.62; 5 -13.97,-7.62; 6 -11.43,-7.62; 7 -8.89,-7.62; 8 -6.35,-7.62; 9 -3.81,-7.62; 10 -1.27,-7.62; 11 1.27,-7.62; 12 3.81,-7.62; 13 6.35,-7.62; 14 8.89,-7.62; 15 11.43,-7.62; 16 13.97,-7.62; 17 16.51,-7.62; 18 19.05,-7.62; 19 21.59,-7.62; 20 24.13,-7.62; 21 24.13,7.62; 22 21.59,7.62; 23 19.05,7.62; 24 16.51,7.62; 25 13.97,7.62; 26 11.43,7.62; 27 8.89,7.62; 28 6.35,7.62; 29 3.81,7.62; 30 1.27,7.62; 31 -1.27,7.62; 32 -3.81,7.62; 33 -6.35,7.62; 34 -8.89,7.62; 35 -11.43,7.62; 36 -13.97,7.62; 37 -16.51,7.62; 38 -19.05,7.62; 39 -21.59,7.62; 40 -24.13,7.62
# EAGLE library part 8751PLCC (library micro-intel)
MICROCOMPUTER/PERIPHERAL DEVICE

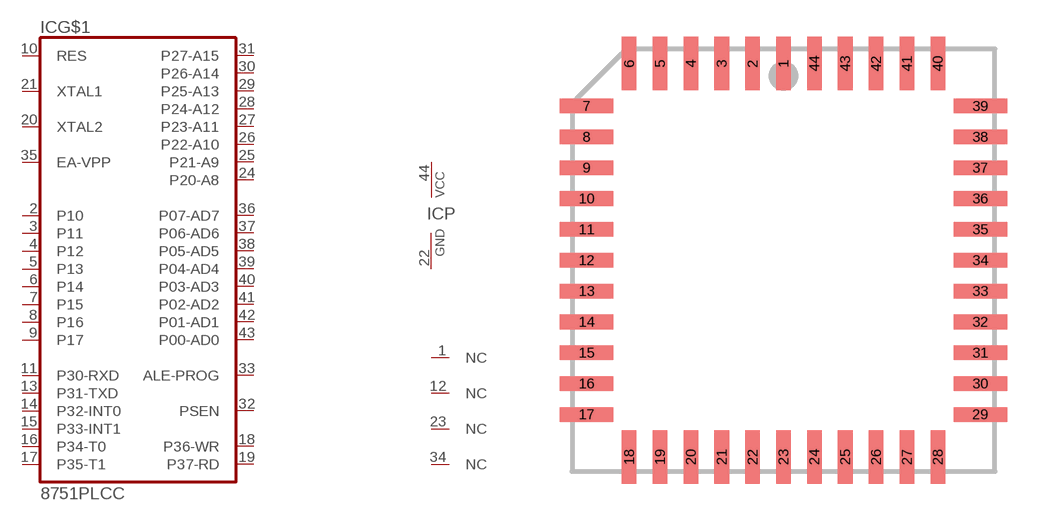
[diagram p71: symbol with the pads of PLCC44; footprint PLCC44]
Designator prefix IC; gates G$1=8751PLCC NC2=NC NC3=NC NC4=NC P=PWRN NC1=NC

## 8751PLCC (OC_FARNELL: unknown; OC_NEWARK: unknown)  [PLCC44]
1  NC1:NC  nc
2  G$1:P10
3  G$1:P11
4  G$1:P12
5  G$1:P13
6  G$1:P14
7  G$1:P15
8  G$1:P16
9  G$1:P17
10  G$1:RES  in
11  G$1:P30-RXD
12  NC2:NC  nc
13  G$1:P31-TXD
14  G$1:P32-INT0
15  G$1:P33-INT1
16  G$1:P34-T0
17  G$1:P35-T1
18  G$1:P36-WR
19  G$1:P37-RD
20  G$1:XTAL2  in
21  G$1:XTAL1  in
22  P:GND  pwr
23  NC3:NC  nc
24  G$1:P20-A8
25  G$1:P21-A9
26  G$1:P22-A10
27  G$1:P23-A11
28  G$1:P24-A12
29  G$1:P25-A13
30  G$1:P26-A14
31  G$1:P27-A15
32  G$1:PSEN  out
33  G$1:ALE-PROG  out
34  NC4:NC  nc
35  G$1:EA-VPP  in
36  G$1:P07-AD7
37  G$1:P06-AD6
38  G$1:P05-AD5
39  G$1:P04-AD4
40  G$1:P03-AD3
41  G$1:P02-AD2
42  G$1:P01-AD1
43  G$1:P00-AD0
44  P:VCC  pwr

## Footprint PLCC44 (pad centres in mm)
PLASTIC LEADED CHIP CARRIER square
smd 0.6 x 2.2: 1 0,8.1; 2 -1.27,8.1; 3 -2.54,8.1; 4 -3.81,8.1; 5 -5.08,8.1; 6 -6.35,8.1; 18 -6.35,-8.1; 19 -5.08,-8.1; 20 -3.81,-8.1; 21 -2.54,-8.1; 22 -1.27,-8.1; 23 0,-8.1; 24 1.27,-8.1; 25 2.54,-8.1; 26 3.81,-8.1; 27 5.08,-8.1; 28 6.35,-8.1; 40 6.35,8.1; 41 5.08,8.1; 42 3.81,8.1; 43 2.54,8.1; 44 1.27,8.1
smd 2.2 x 0.6: 7 -8.1,6.35; 8 -8.1,5.08; 9 -8.1,3.81; 10 -8.1,2.54; 11 -8.1,1.27; 12 -8.1,0; 13 -8.1,-1.27; 14 -8.1,-2.54; 15 -8.1,-3.81; 16 -8.1,-5.08; 17 -8.1,-6.35; 29 8.1,-6.35; 30 8.1,-5.08; 31 8.1,-3.81; 32 8.1,-2.54; 33 8.1,-1.27; 34 8.1,0; 35 8.1,1.27; 36 8.1,2.54; 37 8.1,3.81; 38 8.1,5.08; 39 8.1,6.35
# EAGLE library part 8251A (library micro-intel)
Universal Syncronous/Asynchronous Receiver/Transmitter (USART) Source: http://www.alldatasheet.com/datasheet-pdf/pdf/INTEL/8251A.html

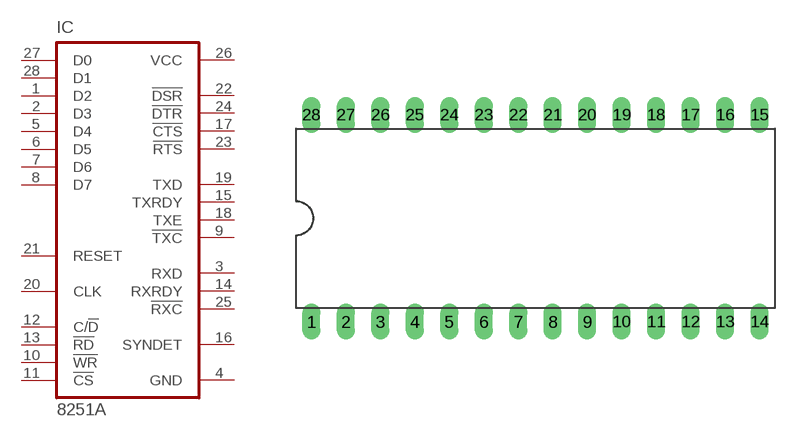
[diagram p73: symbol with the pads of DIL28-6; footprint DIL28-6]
Designator prefix IC

## 8251A (OC_FARNELL: unknown; OC_NEWARK: unknown)  [DIL28-6]
1  D2  hiz
2  D3  hiz
3  RXD  in
4  GND  pwr
5  D4  hiz
6  D5  hiz
7  D6  hiz
8  D7  hiz
9  !TXC  in
10  !WR  in
11  !CS  in
12  C/!D  in
13  !RD  in
14  RXRDY  out
15  TXRDY  out
16  SYNDET
17  !CTS  in
18  TXE  out
19  TXD  out
20  CLK  in
21  RESET  in
22  !DSR  in
23  !RTS  out
24  !DTR  out
25  !RXC  in
26  VCC  pwr
27  D0  hiz
28  D1  hiz

## Footprint DIL28-6 (pad centres in mm)
Dual In Line Package 0.6 inch
drill 0.813 long: 1 -16.51,-7.62; 2 -13.97,-7.62; 3 -11.43,-7.62; 4 -8.89,-7.62; 5 -6.35,-7.62; 6 -3.81,-7.62; 7 -1.27,-7.62; 8 1.27,-7.62; 9 3.81,-7.62; 10 6.35,-7.62; 11 8.89,-7.62; 12 11.43,-7.62; 13 13.97,-7.62; 14 16.51,-7.62; 15 16.51,7.62; 16 13.97,7.62; 17 11.43,7.62; 18 8.89,7.62; 19 6.35,7.62; 20 3.81,7.62; 21 1.27,7.62; 22 -1.27,7.62; 23 -3.81,7.62; 24 -6.35,7.62; 25 -8.89,7.62; 26 -11.43,7.62; 27 -13.97,7.62; 28 -16.51,7.62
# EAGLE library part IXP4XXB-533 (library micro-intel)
Intel XScale® Core Auto generated by 'make-symbol-device-package(bsdl).ulp' Source: IXP4XXB-533.bsdl

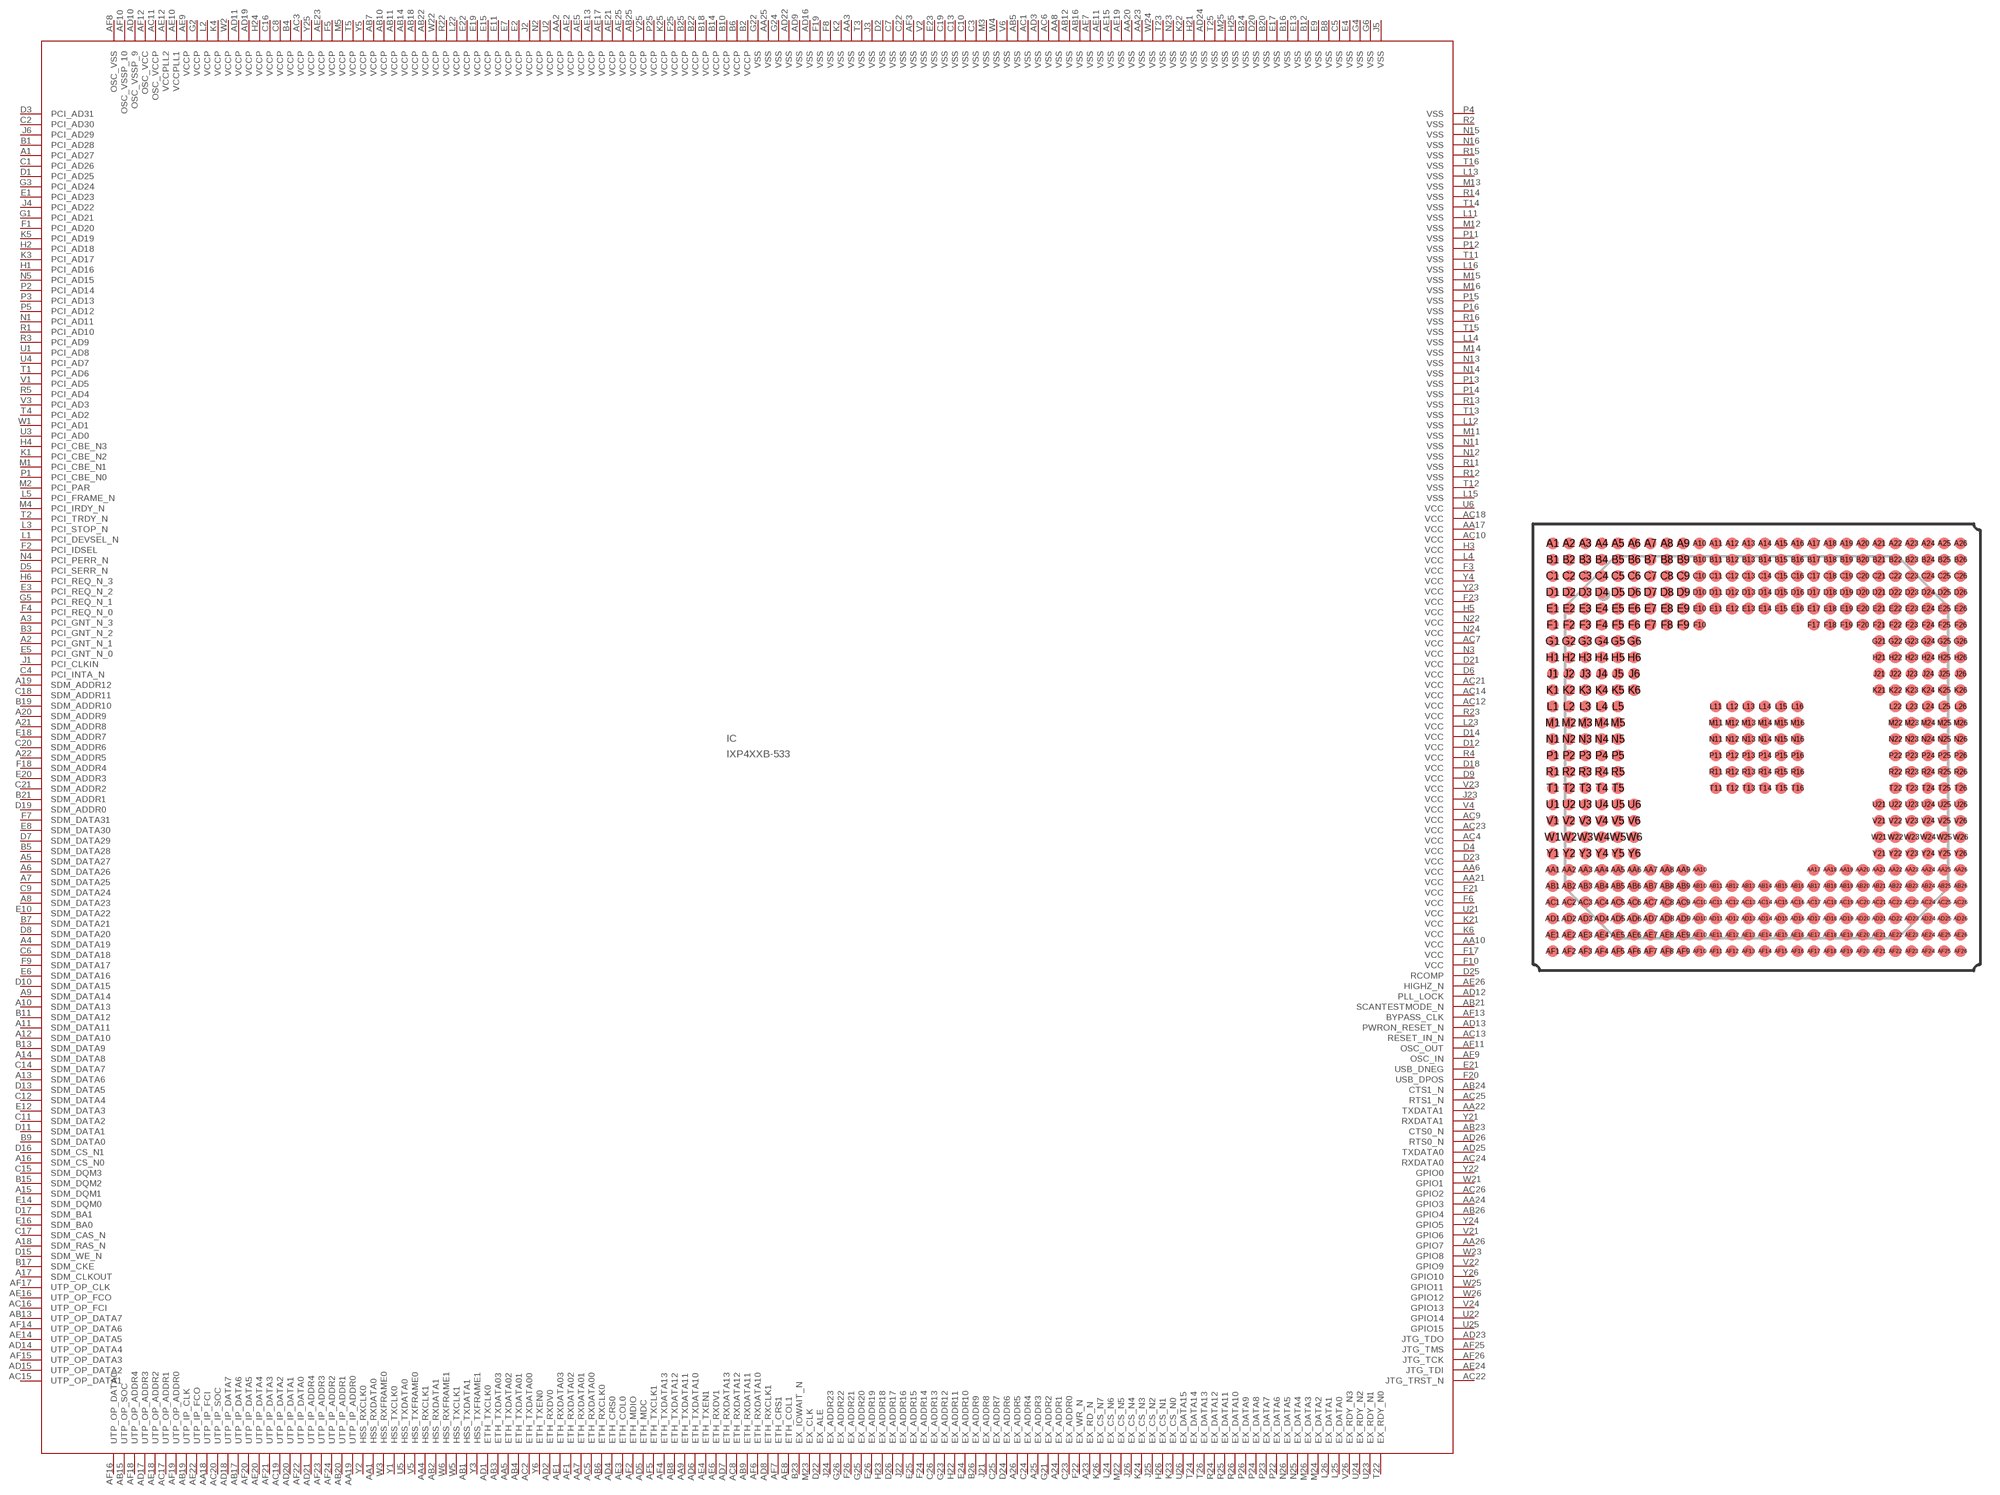
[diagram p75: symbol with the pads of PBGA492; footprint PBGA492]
Designator prefix IC

## IXP4XXB-533 (OC_FARNELL: unknown; OC_NEWARK: unknown)  [PBGA492]
A1  PCI_AD27
A2  PCI_GNT_N_1  out
A3  PCI_GNT_N_3  out
A4  SDM_DATA19  out
A5  SDM_DATA27  out
A6  SDM_DATA26  out
A7  SDM_DATA25  out
A8  SDM_DATA23  out
A9  SDM_DATA14  out
A10  SDM_DATA13  out
A11  SDM_DATA11  out
A12  SDM_DATA10  out
A13  SDM_DATA6  out
A14  SDM_DATA8  out
A15  SDM_DQM1  out
A16  SDM_CS_N0  out
A17  SDM_CLKOUT  out
A18  SDM_RAS_N  out
A19  SDM_ADDR12  out
A20  SDM_ADDR9  out
A21  SDM_ADDR8  out
A22  SDM_ADDR5  out
A23  EX_RD_N  out
A24  EX_ADDR1  out
A25  EX_ADDR3  out
A26  EX_ADDR5  out
AA1  HSS_RXDATA0  in
AA2  VCCP  out
AA3  VSS  out
AA4  HSS_RXCLK1
AA5  ETH_TXDATA02  in
AA6  VCC  out
AA7  ETH_RXDATA01  in
AA8  VSS  out
AA9  ETH_TXDATA11  in
AA10  VCC  out
AA17  VCC  out
AA18  UTP_IP_FCI  in
AA19  UTP_IP_ADDR0  in
AA20  VSS  out
AA21  VCC  out
AA22  TXDATA1  out
AA23  VSS  out
AA24  GPIO3  out
AA25  VSS  out
AA26  GPIO7  out
AB1  HSS_TXDATA1  out
AB2  HSS_RXDATA1  in
AB3  ETH_TXDATA03  in
AB4  ETH_TXDATA01  in
AB5  VSS  out
AB6  ETH_RXCLK0  in
AB7  VCCP  out
AB8  ETH_TXDATA12  in
AB9  ETH_RXDATA11  in
AB10  VCCP  out
AB11  VCCP  out
AB12  VSS  out
AB13  UTP_OP_DATA7  in
AB14  VCCP  out
AB15  UTP_OP_SOC  out
AB16  VSS  out
AB17  UTP_IP_DATA6  in
AB18  VCCP  out
AB19  UTP_IP_CLK  in
AB20  UTP_IP_ADDR1  in
AB21  SCANTESTMODE_N  in
AB22  VCCP  out
AB23  CTS0_N  in
AB24  CTS1_N  in
AB25  VCCP  out
AB26  GPIO4  out
AC1  VSS  out
AC2  ETH_TXDATA00  in
AC3  VCCP  out
AC4  VCC  out
AC5  ETH_RXDATA00  in
AC6  VSS  out
AC7  VCC  out
AC8  ETH_RXDATA12  in
AC9  VCC  out
AC10  VCC  out
AC11  OSC_VCCP  pwr
AC12  VCC  out
AC13  RESET_IN_N  in
AC14  VCC  out
AC15  UTP_OP_DATA1  in
AC16  UTP_OP_FCI  in
AC17  UTP_OP_ADDR1  out
AC18  VCC  out
AC19  UTP_IP_DATA2  in
AC20  UTP_IP_SOC  in
AC21  VCC  out
AC22  JTG_TRST_N  in
AC23  VCC  out
AC24  RXDATA0  in
AC25  RTS1_N  out
AC26  GPIO2  out
AD1  ETH_TXCLK0  in
AD2  ETH_RXDV0  in
AD3  VSS  out
AD4  ETH_CRS0  in
AD5  ETH_MDC
AD6  ETH_TXDATA10  in
AD7  ETH_RXDATA13  in
AD8  ETH_RXCLK1  in
AD9  VSS  out
AD10  OSC_VSSP_9  pwr
AD11  VCCP  out
AD12  PLL_LOCK  out
AD13  PWRON_RESET_N  in
AD14  UTP_OP_DATA4  in
AD15  UTP_OP_DATA2  in
AD16  VSS  out
AD17  UTP_OP_ADDR3  out
AD18  UTP_IP_DATA7  in
AD19  VCCP  out
AD20  UTP_IP_DATA1  in
AD21  UTP_IP_ADDR4  in
AD22  VSS  out
AD23  JTG_TDO  out
AD24  VSS  out
AD25  TXDATA0  out
AD26  RTS0_N  out
AE1  ETH_RXDATA03  in
AE2  VCCP  out
AE3  ETH_COL0  in
AE4  ETH_TXEN1  out
AE5  VCCP  out
AE6  ETH_RXDV1  in
AE7  VSS  out
AE8  ETH_COL1  in
AE9  VCCP  out
AE10  VCCPLL1  pwr
AE11  VSS  out
AE12  VCCPLL2  pwr
AE13  VCCP  out
AE14  UTP_OP_DATA5  in
AE15  VSS  out
AE16  UTP_OP_FCO  out
AE17  VCCP  out
AE18  UTP_OP_ADDR2  out
AE19  VSS  out
AE20  UTP_IP_DATA4  in
AE21  VCCP  out
AE22  UTP_IP_FCO  out
AE23  VCCP  out
AE24  JTG_TDI  in
AE25  VCCP  out
AE26  HIGHZ_N  in
AF1  ETH_RXDATA02  in
AF2  ETH_MDIO
AF3  VSS  out
AF4  ETH_TXDATA13  in
AF5  ETH_TXCLK1  in
AF6  ETH_RXDATA10  in
AF7  ETH_CRS1  in
AF8  OSC_VSS  pwr
AF9  OSC_IN  in
AF10  OSC_VSSP_10  pwr
AF11  OSC_OUT  out
AF12  OSC_VCC  pwr
AF13  BYPASS_CLK  in
AF14  UTP_OP_DATA6  in
AF15  UTP_OP_DATA3  in
AF16  UTP_OP_DATA0  in
AF17  UTP_OP_CLK  in
AF18  UTP_OP_ADDR4  out
AF19  UTP_OP_ADDR0  out
AF20  UTP_IP_DATA5  in
AF21  UTP_IP_DATA3  in
AF22  UTP_IP_DATA0  in
AF23  UTP_IP_ADDR3  in
AF24  UTP_IP_ADDR2  in
AF25  JTG_TMS  in
AF26  JTG_TCK  in
B1  PCI_AD28
B2  VCCP  out
B3  PCI_GNT_N_2  out
B4  VCCP  out
B5  SDM_DATA28  out
B6  VCCP  out
B7  SDM_DATA21  out
B8  VSS  out
B9  SDM_DATA0  out
B10  VCCP  out
B11  SDM_DATA12  out
B12  VSS  out
B13  SDM_DATA9  out
B14  VCCP  out
B15  SDM_DQM2  out
B16  VSS  out
B17  SDM_CKE  out
B18  VCCP  out
B19  SDM_ADDR10  out
B20  VSS  out
B21  SDM_ADDR1  out
B22  VCCP  out
B23  EX_IOWAIT_N  in
B24  VSS  out
B25  VCCP  out
B26  EX_ADDR9  out
C1  PCI_AD26
C2  PCI_AD30
C3  VSS  out
C4  PCI_INTA_N  out
C5  VSS  out
C6  SDM_DATA18  out
C7  VSS  out
C8  VCCP  out
C9  SDM_DATA24  out
C10  VSS  out
C11  SDM_DATA2  out
C12  SDM_DATA4  out
C13  VSS  out
C14  SDM_DATA7  out
C15  SDM_DQM3  out
C16  VCCP  out
C17  SDM_CAS_N  out
C18  SDM_ADDR11  out
C19  VSS  out
C20  SDM_ADDR6  out
C21  SDM_ADDR2  out
C22  VSS  out
C23  EX_ADDR0  out
C24  EX_ADDR4  out
C25  EX_ADDR7  out
C26  EX_ADDR13  out
D1  PCI_AD25
D2  VSS  out
D3  PCI_AD31
D4  VCC  out
D5  PCI_SERR_N
D6  VCC  out
D7  SDM_DATA29  out
D8  SDM_DATA20  out
D9  VCC  out
D10  SDM_DATA15  out
D11  SDM_DATA1  out
D12  VCC  out
D13  SDM_DATA5  out
D14  VCC  out
D15  SDM_WE_N  out
D16  SDM_CS_N1  out
D17  SDM_BA1  out
D18  VCC  out
D19  SDM_ADDR0  out
D20  VSS  out
D21  VCC  out
D22  EX_ALE  out
D23  VCC  out
D24  EX_ADDR6  out
D25  RCOMP  out
D26  EX_ADDR17  out
E1  PCI_AD23
E2  VCCP  out
E3  PCI_REQ_N_2  in
E4  VSS  out
E5  PCI_GNT_N_0
E6  SDM_DATA16  out
E7  VCCP  out
E8  SDM_DATA30  out
E9  VSS  out
E10  SDM_DATA22  out
E11  VCCP  out
E12  SDM_DATA3  out
E13  VSS  out
E14  SDM_DQM0  out
E15  VCCP  out
E16  SDM_BA0  out
E17  VSS  out
E18  SDM_ADDR7  out
E19  VCCP  out
E20  SDM_ADDR3  out
E21  USB_DNEG
E22  VCCP  out
E23  VSS  out
E24  EX_ADDR10  out
E25  EX_ADDR15  out
E26  EX_ADDR19  out
F1  PCI_AD20
F2  PCI_IDSEL  in
F3  VCC  out
F4  PCI_REQ_N_0
F5  VCCP  out
F6  VCC  out
F7  SDM_DATA31  out
F8  VSS  out
F9  SDM_DATA17  out
F10  VCC  out
F17  VCC  out
F18  SDM_ADDR4  out
F19  VSS  out
F20  USB_DPOS
F21  VCC  out
F22  EX_WR_N  out
F23  VCC  out
F24  EX_ADDR14  out
F25  VCCP  out
F26  EX_ADDR21  out
G1  PCI_AD21
G2  VCCP  out
G3  PCI_AD24
G4  VSS  out
G5  PCI_REQ_N_1  in
G6  VSS  out
G21  EX_ADDR2  out
G22  VSS  out
G23  EX_ADDR12  out
G24  VSS  out
G25  EX_ADDR20  out
G26  EX_ADDR22  out
H1  PCI_AD16
H2  PCI_AD18
H3  VCC  out
H4  PCI_CBE_N3
H5  VCC  out
H6  PCI_REQ_N_3  in
H21  VSS  out
H22  EX_ADDR11  out
H23  EX_ADDR18  out
H24  VCCP  out
H25  VSS  out
H26  EX_CS_N1  out
J1  PCI_CLKIN  in
J2  VCCP  out
J3  VSS  out
J4  PCI_AD22
J5  VSS  out
J6  PCI_AD29
J21  EX_ADDR8  out
J22  EX_ADDR16  out
J23  VCC  out
J24  EX_ADDR23  out
J25  EX_CS_N2  out
J26  EX_CS_N4  out
K1  PCI_CBE_N2
K2  VSS  out
K3  PCI_AD17
K4  VCCP  out
K5  PCI_AD19
K6  VCC  out
K21  VCC  out
K22  VSS  out
K23  EX_CS_N0  out
K24  EX_CS_N3  out
K25  VCCP  out
K26  EX_CS_N7  out
L1  PCI_DEVSEL_N
L2  VCCP  out
L3  PCI_STOP_N
L4  VCC  out
L5  PCI_FRAME_N
L11  VSS  out
L12  VSS  out
L13  VSS  out
L14  VSS  out
L15  VSS  out
L16  VSS  out
L22  VCCP  out
L23  VCC  out
L24  EX_CS_N6  out
L25  EX_DATA0  out
L26  EX_DATA1  out
M1  PCI_CBE_N1
M2  PCI_PAR
M3  VSS  out
M4  PCI_IRDY_N
M5  VCCP  out
M11  VSS  out
M12  VSS  out
M13  VSS  out
M14  VSS  out
M15  VSS  out
M16  VSS  out
M22  EX_CS_N5  out
M23  EX_CLK  in
M24  EX_DATA2  out
M25  VSS  out
M26  EX_DATA3  out
N1  PCI_AD11
N2  VCCP  out
N3  VCC  out
N4  PCI_PERR_N
N5  PCI_AD15
N11  VSS  out
N12  VSS  out
N13  VSS  out
N14  VSS  out
N15  VSS  out
N16  VSS  out
N22  VCC  out
N23  VSS  out
N24  VCC  out
N25  EX_DATA4  out
N26  EX_DATA5  out
P1  PCI_CBE_N0
P2  PCI_AD14
P3  PCI_AD13
P4  VSS  out
P5  PCI_AD12
P11  VSS  out
P12  VSS  out
P13  VSS  out
P14  VSS  out
P15  VSS  out
P16  VSS  out
P22  EX_DATA6  out
P23  EX_DATA7  out
P24  EX_DATA8  out
P25  VCCP  out
P26  EX_DATA9  out
R1  PCI_AD10
R2  VSS  out
R3  PCI_AD9
R4  VCC  out
R5  PCI_AD4
R11  VSS  out
R12  VSS  out
R13  VSS  out
R14  VSS  out
R15  VSS  out
R16  VSS  out
R22  VCCP  out
R23  VCC  out
R24  EX_DATA12  out
R25  EX_DATA11  out
R26  EX_DATA10  out
T1  PCI_AD6
T2  PCI_TRDY_N
T3  VSS  out
T4  PCI_AD2
T5  VCCP  out
T11  VSS  out
T12  VSS  out
T13  VSS  out
T14  VSS  out
T15  VSS  out
T16  VSS  out
T22  EX_RDY_N0  out
T23  VSS  out
T24  EX_DATA14  out
T25  VSS  out
T26  EX_DATA13  out
U1  PCI_AD8
U2  VCCP  out
U3  PCI_AD0
U4  PCI_AD7
U5  HSS_TXDATA0  out
U6  VCC  out
U21  VCC  out
U22  GPIO14  out
U23  EX_RDY_N1  out
U24  EX_RDY_N2  out
U25  GPIO15  out
U26  EX_DATA15  out
V1  PCI_AD5
V2  VSS  out
V3  PCI_AD3
V4  VCC  out
V5  HSS_TXFRAME0
V6  VSS  out
V21  GPIO6  out
V22  GPIO9  out
V23  VCC  out
V24  GPIO13  out
V25  VCCP  out
V26  EX_RDY_N3  out
W1  PCI_AD1
W2  VCCP  out
W3  HSS_RXFRAME0
W4  VSS  out
W5  HSS_TXCLK1
W6  HSS_RXFRAME1
W21  GPIO1  out
W22  VCCP  out
W23  GPIO8  out
W24  VSS  out
W25  GPIO11  out
W26  GPIO12  out
Y1  HSS_TXCLK0
Y2  HSS_RXCLK0
Y3  HSS_TXFRAME1
Y4  VCC  out
Y5  VCCP  out
Y6  ETH_TXEN0  out
Y21  RXDATA1  in
Y22  GPIO0  out
Y23  VCC  out
Y24  GPIO5  out
Y25  VCCP  out
Y26  GPIO10  out

## Footprint PBGA492 (pad centres in mm)
492-Pin Lead PBGA (plastic ball grid array) Source: ftp://download.intel.com/design/network/datashts/25247904.pdf
smd 0.9 x 0.9: A1 -15.875,15.875; A2 -14.605,15.875; A3 -13.335,15.875; A4 -12.065,15.875; A5 -10.795,15.875; A6 -9.525,15.875; A7 -8.255,15.875; A8 -6.985,15.875; A9 -5.715,15.875; A10 -4.445,15.875; A11 -3.175,15.875; A12 -1.905,15.875; A13 -0.635,15.875; A14 0.635,15.875; A15 1.905,15.875; A16 3.175,15.875; A17 4.445,15.875; A18 5.715,15.875; A19 6.985,15.875; A20 8.255,15.875; A21 9.525,15.875; A22 10.795,15.875; A23 12.065,15.875; A24 13.335,15.875; A25 14.605,15.875; A26 15.875,15.875; AA1 -15.875,-9.525; AA2 -14.605,-9.525; AA3 -13.335,-9.525; AA4 -12.065,-9.525; AA5 -10.795,-9.525; AA6 -9.525,-9.525; AA7 -8.255,-9.525; AA8 -6.985,-9.525; AA9 -5.715,-9.525; AA10 -4.445,-9.525; AA17 4.445,-9.525; AA18 5.715,-9.525; AA19 6.985,-9.525; AA20 8.255,-9.525; AA21 9.525,-9.525; AA22 10.795,-9.525; AA23 12.065,-9.525; AA24 13.335,-9.525; AA25 14.605,-9.525; AA26 15.875,-9.525; AB1 -15.875,-10.795; AB2 -14.605,-10.795; AB3 -13.335,-10.795; AB4 -12.065,-10.795; AB5 -10.795,-10.795; AB6 -9.525,-10.795; AB7 -8.255,-10.795; AB8 -6.985,-10.795; AB9 -5.715,-10.795; AB10 -4.445,-10.795; AB11 -3.175,-10.795; AB12 -1.905,-10.795; AB13 -0.635,-10.795; AB14 0.635,-10.795; AB15 1.905,-10.795; AB16 3.175,-10.795; AB17 4.445,-10.795; AB18 5.715,-10.795; AB19 6.985,-10.795; AB20 8.255,-10.795; AB21 9.525,-10.795; AB22 10.795,-10.795; AB23 12.065,-10.795; AB24 13.335,-10.795; AB25 14.605,-10.795; AB26 15.875,-10.795; AC1 -15.875,-12.065; AC2 -14.605,-12.065; AC3 -13.335,-12.065; AC4 -12.065,-12.065; AC5 -10.795,-12.065; AC6 -9.525,-12.065; AC7 -8.255,-12.065; AC8 -6.985,-12.065; AC9 -5.715,-12.065; AC10 -4.445,-12.065; AC11 -3.175,-12.065; AC12 -1.905,-12.065; AC13 -0.635,-12.065; AC14 0.635,-12.065; AC15 1.905,-12.065; AC16 3.175,-12.065; AC17 4.445,-12.065; AC18 5.715,-12.065; AC19 6.985,-12.065; AC20 8.255,-12.065; AC21 9.525,-12.065; AC22 10.795,-12.065; AC23 12.065,-12.065; AC24 13.335,-12.065; AC25 14.605,-12.065; AC26 15.875,-12.065; AD1 -15.875,-13.335; AD2 -14.605,-13.335; AD3 -13.335,-13.335; AD4 -12.065,-13.335; AD5 -10.795,-13.335; AD6 -9.525,-13.335; AD7 -8.255,-13.335; AD8 -6.985,-13.335; AD9 -5.715,-13.335; AD10 -4.445,-13.335; AD11 -3.175,-13.335; AD12 -1.905,-13.335; AD13 -0.635,-13.335; AD14 0.635,-13.335; AD15 1.905,-13.335; AD16 3.175,-13.335; AD17 4.445,-13.335; AD18 5.715,-13.335; AD19 6.985,-13.335; AD20 8.255,-13.335; AD21 9.525,-13.335; AD22 10.795,-13.335; AD23 12.065,-13.335; AD24 13.335,-13.335; AD25 14.605,-13.335; AD26 15.875,-13.335; AE1 -15.875,-14.605; AE2 -14.605,-14.605; AE3 -13.335,-14.605; AE4 -12.065,-14.605; AE5 -10.795,-14.605; AE6 -9.525,-14.605; AE7 -8.255,-14.605; AE8 -6.985,-14.605; AE9 -5.715,-14.605; AE10 -4.445,-14.605; AE11 -3.175,-14.605; AE12 -1.905,-14.605; AE13 -0.635,-14.605; AE14 0.635,-14.605; AE15 1.905,-14.605; AE16 3.175,-14.605; AE17 4.445,-14.605; AE18 5.715,-14.605; AE19 6.985,-14.605; AE20 8.255,-14.605; AE21 9.525,-14.605; AE22 10.795,-14.605; AE23 12.065,-14.605; AE24 13.335,-14.605; AE25 14.605,-14.605; AE26 15.875,-14.605; AF1 -15.875,-15.875; AF2 -14.605,-15.875; AF3 -13.335,-15.875; AF4 -12.065,-15.875; AF5 -10.795,-15.875; AF6 -9.525,-15.875; AF7 -8.255,-15.875; AF8 -6.985,-15.875; AF9 -5.715,-15.875; AF10 -4.445,-15.875; AF11 -3.175,-15.875; AF12 -1.905,-15.875; AF13 -0.635,-15.875; AF14 0.635,-15.875; AF15 1.905,-15.875; AF16 3.175,-15.875; AF17 4.445,-15.875; AF18 5.715,-15.875; AF19 6.985,-15.875; AF20 8.255,-15.875; AF21 9.525,-15.875; AF22 10.795,-15.875; AF23 12.065,-15.875; AF24 13.335,-15.875; AF25 14.605,-15.875; AF26 15.875,-15.875; B1 -15.875,14.605; B2 -14.605,14.605; B3 -13.335,14.605; B4 -12.065,14.605; B5 -10.795,14.605; B6 -9.525,14.605; B7 -8.255,14.605; B8 -6.985,14.605; B9 -5.715,14.605; B10 -4.445,14.605; B11 -3.175,14.605; B12 -1.905,14.605; B13 -0.635,14.605; B14 0.635,14.605; B15 1.905,14.605; B16 3.175,14.605; B17 4.445,14.605; B18 5.715,14.605; B19 6.985,14.605; B20 8.255,14.605; B21 9.525,14.605; B22 10.795,14.605; B23 12.065,14.605; B24 13.335,14.605; B25 14.605,14.605; B26 15.875,14.605; C1 -15.875,13.335; C2 -14.605,13.335; C3 -13.335,13.335; C4 -12.065,13.335; C5 -10.795,13.335; C6 -9.525,13.335; C7 -8.255,13.335; C8 -6.985,13.335; C9 -5.715,13.335; C10 -4.445,13.335; C11 -3.175,13.335; C12 -1.905,13.335; C13 -0.635,13.335; C14 0.635,13.335; C15 1.905,13.335; C16 3.175,13.335; C17 4.445,13.335; C18 5.715,13.335; C19 6.985,13.335; C20 8.255,13.335; C21 9.525,13.335; C22 10.795,13.335; C23 12.065,13.335; C24 13.335,13.335; C25 14.605,13.335; C26 15.875,13.335; D1 -15.875,12.065; D2 -14.605,12.065; D3 -13.335,12.065; D4 -12.065,12.065; D5 -10.795,12.065; D6 -9.525,12.065; D7 -8.255,12.065; D8 -6.985,12.065; D9 -5.715,12.065; D10 -4.445,12.065; D11 -3.175,12.065; D12 -1.905,12.065; D13 -0.635,12.065; D14 0.635,12.065; D15 1.905,12.065; D16 3.175,12.065; D17 4.445,12.065; D18 5.715,12.065; D19 6.985,12.065; D20 8.255,12.065; D21 9.525,12.065; D22 10.795,12.065; D23 12.065,12.065; D24 13.335,12.065; D25 14.605,12.065; D26 15.875,12.065; E1 -15.875,10.795; E2 -14.605,10.795; E3 -13.335,10.795; E4 -12.065,10.795; E5 -10.795,10.795; E6 -9.525,10.795; E7 -8.255,10.795; E8 -6.985,10.795; E9 -5.715,10.795; E10 -4.445,10.795; E11 -3.175,10.795; E12 -1.905,10.795; E13 -0.635,10.795; E14 0.635,10.795; E15 1.905,10.795; E16 3.175,10.795; E17 4.445,10.795; E18 5.715,10.795; E19 6.985,10.795; E20 8.255,10.795; E21 9.525,10.795; E22 10.795,10.795; E23 12.065,10.795; E24 13.335,10.795; E25 14.605,10.795; E26 15.875,10.795; F1 -15.875,9.525; F2 -14.605,9.525; F3 -13.335,9.525; F4 -12.065,9.525; F5 -10.795,9.525; F6 -9.525,9.525; F7 -8.255,9.525; F8 -6.985,9.525; F9 -5.715,9.525; F10 -4.445,9.525; F17 4.445,9.525; F18 5.715,9.525; F19 6.985,9.525; F20 8.255,9.525; F21 9.525,9.525; F22 10.795,9.525; F23 12.065,9.525; F24 13.335,9.525; F25 14.605,9.525; F26 15.875,9.525; G1 -15.875,8.255; G2 -14.605,8.255; G3 -13.335,8.255; G4 -12.065,8.255; G5 -10.795,8.255; G6 -9.525,8.255; G21 9.525,8.255; G22 10.795,8.255; G23 12.065,8.255; G24 13.335,8.255; G25 14.605,8.255; G26 15.875,8.255; H1 -15.875,6.985; H2 -14.605,6.985; H3 -13.335,6.985; H4 -12.065,6.985; H5 -10.795,6.985; H6 -9.525,6.985; H21 9.525,6.985; H22 10.795,6.985; H23 12.065,6.985; H24 13.335,6.985; H25 14.605,6.985; H26 15.875,6.985; J1 -15.875,5.715; J2 -14.605,5.715; J3 -13.335,5.715; J4 -12.065,5.715; J5 -10.795,5.715; J6 -9.525,5.715; J21 9.525,5.715; J22 10.795,5.715; J23 12.065,5.715; J24 13.335,5.715; J25 14.605,5.715; J26 15.875,5.715; K1 -15.875,4.445; K2 -14.605,4.445; K3 -13.335,4.445; K4 -12.065,4.445; K5 -10.795,4.445; K6 -9.525,4.445; K21 9.525,4.445; K22 10.795,4.445; K23 12.065,4.445; K24 13.335,4.445; K25 14.605,4.445; K26 15.875,4.445; L1 -15.875,3.175; L2 -14.605,3.175; L3 -13.335,3.175; L4 -12.065,3.175; L5 -10.795,3.175; L11 -3.175,3.175; L12 -1.905,3.175; L13 -0.635,3.175; L14 0.635,3.175; L15 1.905,3.175; L16 3.175,3.175; L22 10.795,3.175; L23 12.065,3.175; L24 13.335,3.175; L25 14.605,3.175; L26 15.875,3.175; M1 -15.875,1.905; M2 -14.605,1.905; M3 -13.335,1.905; M4 -12.065,1.905; M5 -10.795,1.905; M11 -3.175,1.905; M12 -1.905,1.905; M13 -0.635,1.905; M14 0.635,1.905; M15 1.905,1.905; M16 3.175,1.905; M22 10.795,1.905; M23 12.065,1.905; M24 13.335,1.905; M25 14.605,1.905; M26 15.875,1.905; N1 -15.875,0.635; N2 -14.605,0.635; N3 -13.335,0.635; N4 -12.065,0.635; N5 -10.795,0.635; N11 -3.175,0.635; N12 -1.905,0.635; N13 -0.635,0.635; N14 0.635,0.635; N15 1.905,0.635; N16 3.175,0.635; N22 10.795,0.635; N23 12.065,0.635; N24 13.335,0.635; N25 14.605,0.635; N26 15.875,0.635; P1 -15.875,-0.635; P2 -14.605,-0.635; P3 -13.335,-0.635; P4 -12.065,-0.635; P5 -10.795,-0.635; P11 -3.175,-0.635; P12 -1.905,-0.635; P13 -0.635,-0.635; P14 0.635,-0.635; P15 1.905,-0.635; P16 3.175,-0.635; P22 10.795,-0.635; P23 12.065,-0.635; P24 13.335,-0.635; P25 14.605,-0.635; P26 15.875,-0.635; R1 -15.875,-1.905; R2 -14.605,-1.905; R3 -13.335,-1.905; R4 -12.065,-1.905; R5 -10.795,-1.905; R11 -3.175,-1.905; R12 -1.905,-1.905; R13 -0.635,-1.905; R14 0.635,-1.905; R15 1.905,-1.905; R16 3.175,-1.905; R22 10.795,-1.905; R23 12.065,-1.905; R24 13.335,-1.905; R25 14.605,-1.905; R26 15.875,-1.905; T1 -15.875,-3.175; T2 -14.605,-3.175; T3 -13.335,-3.175; T4 -12.065,-3.175; T5 -10.795,-3.175; T11 -3.175,-3.175; T12 -1.905,-3.175; T13 -0.635,-3.175; T14 0.635,-3.175; T15 1.905,-3.175; T16 3.175,-3.175; T22 10.795,-3.175; T23 12.065,-3.175; T24 13.335,-3.175; T25 14.605,-3.175; T26 15.875,-3.175; U1 -15.875,-4.445; U2 -14.605,-4.445; U3 -13.335,-4.445; U4 -12.065,-4.445; U5 -10.795,-4.445; U6 -9.525,-4.445; U21 9.525,-4.445; U22 10.795,-4.445; U23 12.065,-4.445; U24 13.335,-4.445; U25 14.605,-4.445; U26 15.875,-4.445; V1 -15.875,-5.715; V2 -14.605,-5.715; V3 -13.335,-5.715; V4 -12.065,-5.715; V5 -10.795,-5.715; V6 -9.525,-5.715; V21 9.525,-5.715; V22 10.795,-5.715; V23 12.065,-5.715; V24 13.335,-5.715; V25 14.605,-5.715; V26 15.875,-5.715; W1 -15.875,-6.985; W2 -14.605,-6.985; W3 -13.335,-6.985; W4 -12.065,-6.985; W5 -10.795,-6.985; W6 -9.525,-6.985; W21 9.525,-6.985; W22 10.795,-6.985; W23 12.065,-6.985; W24 13.335,-6.985; W25 14.605,-6.985; W26 15.875,-6.985; Y1 -15.875,-8.255; Y2 -14.605,-8.255; Y3 -13.335,-8.255; Y4 -12.065,-8.255; Y5 -10.795,-8.255; Y6 -9.525,-8.255; Y21 9.525,-8.255; Y22 10.795,-8.255; Y23 12.065,-8.255; Y24 13.335,-8.255; Y25 14.605,-8.255; Y26 15.875,-8.255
